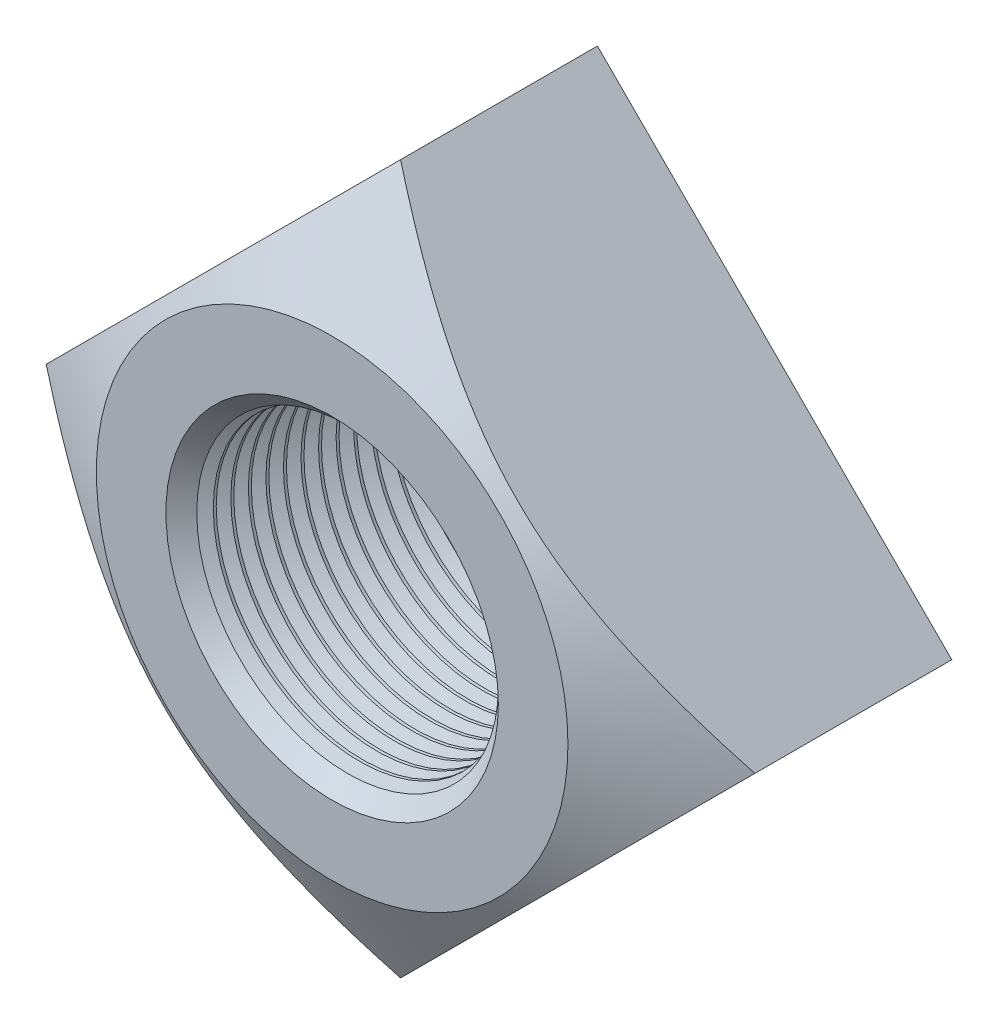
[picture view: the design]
ISO-10303-21;
HEADER;
FILE_DESCRIPTION(('STEP AP214'),'2;1');
FILE_NAME('part.step','',(''),(''),'','','');
FILE_SCHEMA(('AUTOMOTIVE_DESIGN { 1 0 10303 214 1 1 1 1 }'));
ENDSEC;
DATA;
#1=APPLICATION_CONTEXT('core data for automotive mechanical design processes');
#2=APPLICATION_PROTOCOL_DEFINITION('international standard','automotive_design',2000,#1);
#3=PRODUCT_CONTEXT('',#1,'mechanical');
#4=PRODUCT('Part','Part','',(#3));
#5=PRODUCT_RELATED_PRODUCT_CATEGORY('part','',(#4));
#6=PRODUCT_DEFINITION_FORMATION('','',#4);
#7=PRODUCT_DEFINITION_CONTEXT('part definition',#1,'design');
#8=PRODUCT_DEFINITION('design','',#6,#7);
#9=PRODUCT_DEFINITION_SHAPE('','',#8);
#10=(LENGTH_UNIT() NAMED_UNIT(*) SI_UNIT(.MILLI.,.METRE.));
#11=(NAMED_UNIT(*) PLANE_ANGLE_UNIT() SI_UNIT($,.RADIAN.));
#12=(NAMED_UNIT(*) SI_UNIT($,.STERADIAN.) SOLID_ANGLE_UNIT());
#13=UNCERTAINTY_MEASURE_WITH_UNIT(LENGTH_MEASURE(1.E-05),#10,'distance_accuracy_value','');
#14=(GEOMETRIC_REPRESENTATION_CONTEXT(3) GLOBAL_UNCERTAINTY_ASSIGNED_CONTEXT((#13)) GLOBAL_UNIT_ASSIGNED_CONTEXT((#10,
#11,#12)) REPRESENTATION_CONTEXT('',''));
#15=CARTESIAN_POINT('',(0.,0.,0.));
#16=DIRECTION('',(0.,0.,1.));
#17=DIRECTION('',(1.,0.,0.));
#18=AXIS2_PLACEMENT_3D('',#15,#16,#17);
#19=CARTESIAN_POINT('',(0.,0.,-18.));
#20=DIRECTION('',(0.,0.,1.));
#21=DIRECTION('',(1.,0.,0.));
#22=AXIS2_PLACEMENT_3D('',#19,#20,#21);
#23=CYLINDRICAL_SURFACE('',#22,9.9175);
#24=CARTESIAN_POINT('',(0.,0.,-16.64));
#25=DIRECTION('',(0.,0.,1.));
#26=DIRECTION('',(1.,0.,0.));
#27=AXIS2_PLACEMENT_3D('',#24,#25,#26);
#28=CIRCLE('',#27,9.9175);
#29=CARTESIAN_POINT('',(-9.9175,0.,-16.64));
#30=VERTEX_POINT('',#29);
#31=EDGE_CURVE('E50',#30,#30,#28,.F.);
#32=ORIENTED_EDGE('',*,*,#31,.T.);
#33=EDGE_LOOP('',(#32));
#34=FACE_BOUND('',#33,.T.);
#35=CARTESIAN_POINT('',(0.,0.,-16.137075));
#36=DIRECTION('',(0.,0.,-1.));
#37=DIRECTION('',(-1.,0.,0.));
#38=AXIS2_PLACEMENT_3D('',#35,#36,#37);
#39=CIRCLE('',#38,9.9175);
#40=CARTESIAN_POINT('',(-9.9175,0.,-16.137075));
#41=VERTEX_POINT('',#40);
#42=EDGE_CURVE('E641',#41,#41,#39,.T.);
#43=ORIENTED_EDGE('',*,*,#42,.F.);
#44=EDGE_LOOP('',(#43));
#45=FACE_BOUND('',#44,.T.);
#46=ADVANCED_FACE('F41',(#34,#45),#23,.F.);
#47=CARTESIAN_POINT('',(0.,0.,-14.946975));
#48=DIRECTION('',(0.,0.,-1.));
#49=DIRECTION('',(-1.,0.,0.));
#50=AXIS2_PLACEMENT_3D('',#47,#48,#49);
#51=CIRCLE('',#50,9.9175);
#52=CARTESIAN_POINT('',(-9.9175,0.,-14.946975));
#53=VERTEX_POINT('',#52);
#54=EDGE_CURVE('E652',#53,#53,#51,.T.);
#55=ORIENTED_EDGE('',*,*,#54,.F.);
#56=EDGE_LOOP('',(#55));
#57=FACE_BOUND('',#56,.T.);
#58=CARTESIAN_POINT('',(0.,0.,-15.145325));
#59=DIRECTION('',(0.,0.,-1.));
#60=DIRECTION('',(-1.,0.,0.));
#61=AXIS2_PLACEMENT_3D('',#58,#59,#60);
#62=CIRCLE('',#61,9.9175);
#63=CARTESIAN_POINT('',(-9.9175,0.,-15.145325));
#64=VERTEX_POINT('',#63);
#65=EDGE_CURVE('E638',#64,#64,#62,.T.);
#66=ORIENTED_EDGE('',*,*,#65,.T.);
#67=EDGE_LOOP('',(#66));
#68=FACE_BOUND('',#67,.T.);
#69=ADVANCED_FACE('F186',(#57,#68),#23,.F.);
#70=CARTESIAN_POINT('',(0.,0.,-13.756875));
#71=DIRECTION('',(0.,0.,-1.));
#72=DIRECTION('',(-1.,0.,0.));
#73=AXIS2_PLACEMENT_3D('',#70,#71,#72);
#74=CIRCLE('',#73,9.9175);
#75=CARTESIAN_POINT('',(-9.9175,0.,-13.756875));
#76=VERTEX_POINT('',#75);
#77=EDGE_CURVE('E661',#76,#76,#74,.T.);
#78=ORIENTED_EDGE('',*,*,#77,.F.);
#79=EDGE_LOOP('',(#78));
#80=FACE_BOUND('',#79,.T.);
#81=CARTESIAN_POINT('',(0.,0.,-13.955225));
#82=DIRECTION('',(0.,0.,-1.));
#83=DIRECTION('',(-1.,0.,0.));
#84=AXIS2_PLACEMENT_3D('',#81,#82,#83);
#85=CIRCLE('',#84,9.9175);
#86=CARTESIAN_POINT('',(-9.9175,0.,-13.955225));
#87=VERTEX_POINT('',#86);
#88=EDGE_CURVE('E646',#87,#87,#85,.T.);
#89=ORIENTED_EDGE('',*,*,#88,.T.);
#90=EDGE_LOOP('',(#89));
#91=FACE_BOUND('',#90,.T.);
#92=ADVANCED_FACE('F192',(#80,#91),#23,.F.);
#93=CARTESIAN_POINT('',(0.,0.,-12.566775));
#94=DIRECTION('',(0.,0.,-1.));
#95=DIRECTION('',(-1.,0.,0.));
#96=AXIS2_PLACEMENT_3D('',#93,#94,#95);
#97=CIRCLE('',#96,9.9175);
#98=CARTESIAN_POINT('',(-9.9175,0.,-12.566775));
#99=VERTEX_POINT('',#98);
#100=EDGE_CURVE('E670',#99,#99,#97,.T.);
#101=ORIENTED_EDGE('',*,*,#100,.F.);
#102=EDGE_LOOP('',(#101));
#103=FACE_BOUND('',#102,.T.);
#104=CARTESIAN_POINT('',(0.,0.,-12.765125));
#105=DIRECTION('',(0.,0.,-1.));
#106=DIRECTION('',(-1.,0.,0.));
#107=AXIS2_PLACEMENT_3D('',#104,#105,#106);
#108=CIRCLE('',#107,9.9175);
#109=CARTESIAN_POINT('',(-9.9175,0.,-12.765125));
#110=VERTEX_POINT('',#109);
#111=EDGE_CURVE('E655',#110,#110,#108,.T.);
#112=ORIENTED_EDGE('',*,*,#111,.T.);
#113=EDGE_LOOP('',(#112));
#114=FACE_BOUND('',#113,.T.);
#115=ADVANCED_FACE('F319',(#103,#114),#23,.F.);
#116=CARTESIAN_POINT('',(0.,0.,-11.376675));
#117=DIRECTION('',(0.,0.,-1.));
#118=DIRECTION('',(-1.,0.,0.));
#119=AXIS2_PLACEMENT_3D('',#116,#117,#118);
#120=CIRCLE('',#119,9.9175);
#121=CARTESIAN_POINT('',(-9.9175,0.,-11.376675));
#122=VERTEX_POINT('',#121);
#123=EDGE_CURVE('E679',#122,#122,#120,.T.);
#124=ORIENTED_EDGE('',*,*,#123,.F.);
#125=EDGE_LOOP('',(#124));
#126=FACE_BOUND('',#125,.T.);
#127=CARTESIAN_POINT('',(0.,0.,-11.575025));
#128=DIRECTION('',(0.,0.,-1.));
#129=DIRECTION('',(-1.,0.,0.));
#130=AXIS2_PLACEMENT_3D('',#127,#128,#129);
#131=CIRCLE('',#130,9.9175);
#132=CARTESIAN_POINT('',(-9.9175,0.,-11.575025));
#133=VERTEX_POINT('',#132);
#134=EDGE_CURVE('E664',#133,#133,#131,.T.);
#135=ORIENTED_EDGE('',*,*,#134,.T.);
#136=EDGE_LOOP('',(#135));
#137=FACE_BOUND('',#136,.T.);
#138=ADVANCED_FACE('F311',(#126,#137),#23,.F.);
#139=CARTESIAN_POINT('',(0.,0.,-10.186575));
#140=DIRECTION('',(0.,0.,-1.));
#141=DIRECTION('',(-1.,0.,0.));
#142=AXIS2_PLACEMENT_3D('',#139,#140,#141);
#143=CIRCLE('',#142,9.9175);
#144=CARTESIAN_POINT('',(-9.9175,0.,-10.186575));
#145=VERTEX_POINT('',#144);
#146=EDGE_CURVE('E688',#145,#145,#143,.T.);
#147=ORIENTED_EDGE('',*,*,#146,.F.);
#148=EDGE_LOOP('',(#147));
#149=FACE_BOUND('',#148,.T.);
#150=CARTESIAN_POINT('',(0.,0.,-10.384925));
#151=DIRECTION('',(0.,0.,-1.));
#152=DIRECTION('',(-1.,0.,0.));
#153=AXIS2_PLACEMENT_3D('',#150,#151,#152);
#154=CIRCLE('',#153,9.9175);
#155=CARTESIAN_POINT('',(-9.9175,0.,-10.384925));
#156=VERTEX_POINT('',#155);
#157=EDGE_CURVE('E673',#156,#156,#154,.T.);
#158=ORIENTED_EDGE('',*,*,#157,.T.);
#159=EDGE_LOOP('',(#158));
#160=FACE_BOUND('',#159,.T.);
#161=ADVANCED_FACE('F302',(#149,#160),#23,.F.);
#162=CARTESIAN_POINT('',(0.,0.,-8.996475));
#163=DIRECTION('',(0.,0.,-1.));
#164=DIRECTION('',(-1.,0.,0.));
#165=AXIS2_PLACEMENT_3D('',#162,#163,#164);
#166=CIRCLE('',#165,9.9175);
#167=CARTESIAN_POINT('',(-9.9175,0.,-8.996475));
#168=VERTEX_POINT('',#167);
#169=EDGE_CURVE('E697',#168,#168,#166,.T.);
#170=ORIENTED_EDGE('',*,*,#169,.F.);
#171=EDGE_LOOP('',(#170));
#172=FACE_BOUND('',#171,.T.);
#173=CARTESIAN_POINT('',(0.,0.,-9.194825));
#174=DIRECTION('',(0.,0.,-1.));
#175=DIRECTION('',(-1.,0.,0.));
#176=AXIS2_PLACEMENT_3D('',#173,#174,#175);
#177=CIRCLE('',#176,9.9175);
#178=CARTESIAN_POINT('',(-9.9175,0.,-9.194825));
#179=VERTEX_POINT('',#178);
#180=EDGE_CURVE('E682',#179,#179,#177,.T.);
#181=ORIENTED_EDGE('',*,*,#180,.T.);
#182=EDGE_LOOP('',(#181));
#183=FACE_BOUND('',#182,.T.);
#184=ADVANCED_FACE('F294',(#172,#183),#23,.F.);
#185=CARTESIAN_POINT('',(0.,0.,-7.806375));
#186=DIRECTION('',(0.,0.,-1.));
#187=DIRECTION('',(-1.,0.,0.));
#188=AXIS2_PLACEMENT_3D('',#185,#186,#187);
#189=CIRCLE('',#188,9.9175);
#190=CARTESIAN_POINT('',(-9.9175,0.,-7.806375));
#191=VERTEX_POINT('',#190);
#192=EDGE_CURVE('E706',#191,#191,#189,.T.);
#193=ORIENTED_EDGE('',*,*,#192,.F.);
#194=EDGE_LOOP('',(#193));
#195=FACE_BOUND('',#194,.T.);
#196=CARTESIAN_POINT('',(0.,0.,-8.004725));
#197=DIRECTION('',(0.,0.,-1.));
#198=DIRECTION('',(-1.,0.,0.));
#199=AXIS2_PLACEMENT_3D('',#196,#197,#198);
#200=CIRCLE('',#199,9.9175);
#201=CARTESIAN_POINT('',(-9.9175,0.,-8.004725));
#202=VERTEX_POINT('',#201);
#203=EDGE_CURVE('E691',#202,#202,#200,.T.);
#204=ORIENTED_EDGE('',*,*,#203,.T.);
#205=EDGE_LOOP('',(#204));
#206=FACE_BOUND('',#205,.T.);
#207=ADVANCED_FACE('F285',(#195,#206),#23,.F.);
#208=CARTESIAN_POINT('',(0.,0.,-6.616275));
#209=DIRECTION('',(0.,0.,-1.));
#210=DIRECTION('',(-1.,0.,0.));
#211=AXIS2_PLACEMENT_3D('',#208,#209,#210);
#212=CIRCLE('',#211,9.9175);
#213=CARTESIAN_POINT('',(-9.9175,0.,-6.616275));
#214=VERTEX_POINT('',#213);
#215=EDGE_CURVE('E715',#214,#214,#212,.T.);
#216=ORIENTED_EDGE('',*,*,#215,.F.);
#217=EDGE_LOOP('',(#216));
#218=FACE_BOUND('',#217,.T.);
#219=CARTESIAN_POINT('',(0.,0.,-6.814625));
#220=DIRECTION('',(0.,0.,-1.));
#221=DIRECTION('',(-1.,0.,0.));
#222=AXIS2_PLACEMENT_3D('',#219,#220,#221);
#223=CIRCLE('',#222,9.9175);
#224=CARTESIAN_POINT('',(-9.9175,0.,-6.814625));
#225=VERTEX_POINT('',#224);
#226=EDGE_CURVE('E700',#225,#225,#223,.T.);
#227=ORIENTED_EDGE('',*,*,#226,.T.);
#228=EDGE_LOOP('',(#227));
#229=FACE_BOUND('',#228,.T.);
#230=ADVANCED_FACE('F277',(#218,#229),#23,.F.);
#231=CARTESIAN_POINT('',(0.,0.,-5.426175));
#232=DIRECTION('',(0.,0.,-1.));
#233=DIRECTION('',(-1.,0.,0.));
#234=AXIS2_PLACEMENT_3D('',#231,#232,#233);
#235=CIRCLE('',#234,9.9175);
#236=CARTESIAN_POINT('',(-9.9175,0.,-5.426175));
#237=VERTEX_POINT('',#236);
#238=EDGE_CURVE('E724',#237,#237,#235,.T.);
#239=ORIENTED_EDGE('',*,*,#238,.F.);
#240=EDGE_LOOP('',(#239));
#241=FACE_BOUND('',#240,.T.);
#242=CARTESIAN_POINT('',(0.,0.,-5.624525));
#243=DIRECTION('',(0.,0.,-1.));
#244=DIRECTION('',(-1.,0.,0.));
#245=AXIS2_PLACEMENT_3D('',#242,#243,#244);
#246=CIRCLE('',#245,9.9175);
#247=CARTESIAN_POINT('',(-9.9175,0.,-5.624525));
#248=VERTEX_POINT('',#247);
#249=EDGE_CURVE('E709',#248,#248,#246,.T.);
#250=ORIENTED_EDGE('',*,*,#249,.T.);
#251=EDGE_LOOP('',(#250));
#252=FACE_BOUND('',#251,.T.);
#253=ADVANCED_FACE('F268',(#241,#252),#23,.F.);
#254=CARTESIAN_POINT('',(0.,0.,-4.236075));
#255=DIRECTION('',(0.,0.,-1.));
#256=DIRECTION('',(-1.,0.,0.));
#257=AXIS2_PLACEMENT_3D('',#254,#255,#256);
#258=CIRCLE('',#257,9.9175);
#259=CARTESIAN_POINT('',(-9.9175,0.,-4.236075));
#260=VERTEX_POINT('',#259);
#261=EDGE_CURVE('E214',#260,#260,#258,.T.);
#262=ORIENTED_EDGE('',*,*,#261,.F.);
#263=EDGE_LOOP('',(#262));
#264=FACE_BOUND('',#263,.T.);
#265=CARTESIAN_POINT('',(0.,0.,-4.434425));
#266=DIRECTION('',(0.,0.,-1.));
#267=DIRECTION('',(-1.,0.,0.));
#268=AXIS2_PLACEMENT_3D('',#265,#266,#267);
#269=CIRCLE('',#268,9.9175);
#270=CARTESIAN_POINT('',(-9.9175,0.,-4.434425));
#271=VERTEX_POINT('',#270);
#272=EDGE_CURVE('E718',#271,#271,#269,.T.);
#273=ORIENTED_EDGE('',*,*,#272,.T.);
#274=EDGE_LOOP('',(#273));
#275=FACE_BOUND('',#274,.T.);
#276=ADVANCED_FACE('F203',(#264,#275),#23,.F.);
#277=CARTESIAN_POINT('',(0.,0.,-3.045975));
#278=DIRECTION('',(0.,0.,-1.));
#279=DIRECTION('',(-1.,0.,0.));
#280=AXIS2_PLACEMENT_3D('',#277,#278,#279);
#281=CIRCLE('',#280,9.9175);
#282=CARTESIAN_POINT('',(-9.9175,0.,-3.045975));
#283=VERTEX_POINT('',#282);
#284=EDGE_CURVE('E217',#283,#283,#281,.T.);
#285=ORIENTED_EDGE('',*,*,#284,.F.);
#286=EDGE_LOOP('',(#285));
#287=FACE_BOUND('',#286,.T.);
#288=CARTESIAN_POINT('',(0.,0.,-3.244325));
#289=DIRECTION('',(0.,0.,-1.));
#290=DIRECTION('',(-1.,0.,0.));
#291=AXIS2_PLACEMENT_3D('',#288,#289,#290);
#292=CIRCLE('',#291,9.9175);
#293=CARTESIAN_POINT('',(-9.9175,0.,-3.244325));
#294=VERTEX_POINT('',#293);
#295=EDGE_CURVE('E727',#294,#294,#292,.T.);
#296=ORIENTED_EDGE('',*,*,#295,.T.);
#297=EDGE_LOOP('',(#296));
#298=FACE_BOUND('',#297,.T.);
#299=ADVANCED_FACE('F195',(#287,#298),#23,.F.);
#300=CARTESIAN_POINT('',(0.,0.,-1.855875));
#301=DIRECTION('',(0.,0.,-1.));
#302=DIRECTION('',(-1.,0.,0.));
#303=AXIS2_PLACEMENT_3D('',#300,#301,#302);
#304=CIRCLE('',#303,9.9175);
#305=CARTESIAN_POINT('',(-9.9175,0.,-1.855875));
#306=VERTEX_POINT('',#305);
#307=EDGE_CURVE('E208',#306,#306,#304,.T.);
#308=ORIENTED_EDGE('',*,*,#307,.F.);
#309=EDGE_LOOP('',(#308));
#310=FACE_BOUND('',#309,.T.);
#311=CARTESIAN_POINT('',(0.,0.,-2.054225));
#312=DIRECTION('',(0.,0.,-1.));
#313=DIRECTION('',(-1.,0.,0.));
#314=AXIS2_PLACEMENT_3D('',#311,#312,#313);
#315=CIRCLE('',#314,9.9175);
#316=CARTESIAN_POINT('',(-9.9175,0.,-2.054225));
#317=VERTEX_POINT('',#316);
#318=EDGE_CURVE('E211',#317,#317,#315,.T.);
#319=ORIENTED_EDGE('',*,*,#318,.T.);
#320=EDGE_LOOP('',(#319));
#321=FACE_BOUND('',#320,.T.);
#322=ADVANCED_FACE('F187',(#310,#321),#23,.F.);
#323=CARTESIAN_POINT('',(0.,0.,-1.36000000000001));
#324=DIRECTION('',(0.,0.,1.));
#325=DIRECTION('',(1.,0.,0.));
#326=AXIS2_PLACEMENT_3D('',#323,#324,#325);
#327=CONICAL_SURFACE('',#326,9.9175,0.785398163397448);
#328=CARTESIAN_POINT('',(0.,0.,0.));
#329=DIRECTION('',(0.,0.,1.));
#330=DIRECTION('',(1.,0.,0.));
#331=AXIS2_PLACEMENT_3D('',#328,#329,#330);
#332=CIRCLE('',#331,11.2775);
#333=CARTESIAN_POINT('',(11.2775,0.,0.));
#334=VERTEX_POINT('',#333);
#335=EDGE_CURVE('E11',#334,#334,#332,.F.);
#336=CARTESIAN_POINT('',(0.,0.,-1.04562784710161));
#337=DIRECTION('',(0.,0.,-1.));
#338=DIRECTION('',(-1.,0.,0.));
#339=AXIS2_PLACEMENT_3D('',#336,#337,#338);
#340=CIRCLE('',#339,10.2318721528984);
#341=CARTESIAN_POINT('',(10.2318721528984,0.,-1.04562784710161));
#342=VERTEX_POINT('',#341);
#343=EDGE_CURVE('E45',#342,#342,#340,.T.);
#344=CARTESIAN_POINT('',(11.2775,0.,0.));
#345=CARTESIAN_POINT('',(11.2666080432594,0.,-0.010891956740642));
#346=CARTESIAN_POINT('',(11.2557160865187,0.,-0.0217839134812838));
#347=CARTESIAN_POINT('',(11.2339321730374,0.,-0.0435678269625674));
#348=CARTESIAN_POINT('',(11.2230402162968,0.,-0.0544597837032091));
#349=CARTESIAN_POINT('',(11.2012563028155,0.,-0.0762436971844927));
#350=CARTESIAN_POINT('',(11.1903643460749,0.,-0.0871356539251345));
#351=CARTESIAN_POINT('',(11.1685804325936,0.,-0.108919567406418));
#352=CARTESIAN_POINT('',(11.157688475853,0.,-0.11981152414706));
#353=CARTESIAN_POINT('',(11.1359045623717,0.,-0.141595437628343));
#354=CARTESIAN_POINT('',(11.125012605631,0.,-0.152487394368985));
#355=CARTESIAN_POINT('',(11.1032286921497,0.,-0.174271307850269));
#356=CARTESIAN_POINT('',(11.0923367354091,0.,-0.18516326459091));
#357=CARTESIAN_POINT('',(11.0705528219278,0.,-0.206947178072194));
#358=CARTESIAN_POINT('',(11.0596608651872,0.,-0.217839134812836));
#359=CARTESIAN_POINT('',(11.0378769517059,0.,-0.23962304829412));
#360=CARTESIAN_POINT('',(11.0269849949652,0.,-0.250515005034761));
#361=CARTESIAN_POINT('',(11.005201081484,0.,-0.272298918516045));
#362=CARTESIAN_POINT('',(10.9943091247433,0.,-0.283190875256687));
#363=CARTESIAN_POINT('',(10.972525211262,0.,-0.30497478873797));
#364=CARTESIAN_POINT('',(10.9616332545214,0.,-0.315866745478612));
#365=CARTESIAN_POINT('',(10.9398493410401,0.,-0.337650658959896));
#366=CARTESIAN_POINT('',(10.9289573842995,0.,-0.348542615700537));
#367=CARTESIAN_POINT('',(10.9071734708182,0.,-0.370326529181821));
#368=CARTESIAN_POINT('',(10.8962815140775,0.,-0.381218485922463));
#369=CARTESIAN_POINT('',(10.8744976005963,0.,-0.403002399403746));
#370=CARTESIAN_POINT('',(10.8636056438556,0.,-0.413894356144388));
#371=CARTESIAN_POINT('',(10.8418217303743,0.,-0.435678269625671));
#372=CARTESIAN_POINT('',(10.8309297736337,0.,-0.446570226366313));
#373=CARTESIAN_POINT('',(10.8091458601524,0.,-0.468354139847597));
#374=CARTESIAN_POINT('',(10.7982539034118,0.,-0.479246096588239));
#375=CARTESIAN_POINT('',(10.7764699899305,0.,-0.501030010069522));
#376=CARTESIAN_POINT('',(10.7655780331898,0.,-0.511921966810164));
#377=CARTESIAN_POINT('',(10.7437941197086,0.,-0.533705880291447));
#378=CARTESIAN_POINT('',(10.7329021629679,0.,-0.544597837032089));
#379=CARTESIAN_POINT('',(10.7111182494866,0.,-0.566381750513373));
#380=CARTESIAN_POINT('',(10.700226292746,0.,-0.577273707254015));
#381=CARTESIAN_POINT('',(10.6784423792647,0.,-0.599057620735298));
#382=CARTESIAN_POINT('',(10.6675504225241,0.,-0.60994957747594));
#383=CARTESIAN_POINT('',(10.6457665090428,0.,-0.631733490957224));
#384=CARTESIAN_POINT('',(10.6348745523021,0.,-0.642625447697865));
#385=CARTESIAN_POINT('',(10.6130906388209,0.,-0.664409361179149));
#386=CARTESIAN_POINT('',(10.6021986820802,0.,-0.675301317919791));
#387=CARTESIAN_POINT('',(10.5804147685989,0.,-0.697085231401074));
#388=CARTESIAN_POINT('',(10.5695228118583,0.,-0.707977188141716));
#389=CARTESIAN_POINT('',(10.547738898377,0.,-0.729761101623));
#390=CARTESIAN_POINT('',(10.5368469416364,0.,-0.740653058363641));
#391=CARTESIAN_POINT('',(10.5150630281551,0.,-0.762436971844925));
#392=CARTESIAN_POINT('',(10.5041710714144,0.,-0.773328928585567));
#393=CARTESIAN_POINT('',(10.4823871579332,0.,-0.79511284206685));
#394=CARTESIAN_POINT('',(10.4714952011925,0.,-0.806004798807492));
#395=CARTESIAN_POINT('',(10.4497112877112,0.,-0.827788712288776));
#396=CARTESIAN_POINT('',(10.4388193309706,0.,-0.838680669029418));
#397=CARTESIAN_POINT('',(10.4170354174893,0.,-0.860464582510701));
#398=CARTESIAN_POINT('',(10.4061434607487,0.,-0.871356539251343));
#399=CARTESIAN_POINT('',(10.3843595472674,0.,-0.893140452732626));
#400=CARTESIAN_POINT('',(10.3734675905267,0.,-0.904032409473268));
#401=CARTESIAN_POINT('',(10.3516836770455,0.,-0.925816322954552));
#402=CARTESIAN_POINT('',(10.3407917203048,0.,-0.936708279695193));
#403=CARTESIAN_POINT('',(10.3190078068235,0.,-0.958492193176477));
#404=CARTESIAN_POINT('',(10.3081158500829,0.,-0.969384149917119));
#405=CARTESIAN_POINT('',(10.2863319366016,0.,-0.991168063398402));
#406=CARTESIAN_POINT('',(10.275439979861,0.,-1.00206002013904));
#407=CARTESIAN_POINT('',(10.2536560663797,0.,-1.02384393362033));
#408=CARTESIAN_POINT('',(10.242764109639,0.,-1.03473589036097));
#409=CARTESIAN_POINT('',(10.2318721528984,0.,-1.04562784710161));
#410=B_SPLINE_CURVE_WITH_KNOTS('',3,(#344,#345,#346,#347,#348,#349,#350,#351,#352,#353,#354,
#355,#356,#357,#358,#359,#360,#361,#362,#363,#364,#365,#366,#367,#368,#369,#370,#371,#372,#373,
#374,#375,#376,#377,#378,#379,#380,#381,#382,#383,#384,#385,#386,#387,#388,#389,#390,#391,#392,
#393,#394,#395,#396,#397,#398,#399,#400,#401,#402,#403,#404,#405,#406,#407,#408,#409),
.UNSPECIFIED.,.F.,.F.,(4,2,2,2,2,2,2,2,2,2,2,2,2,2,2,2,2,2,2,2,2,2,2,2,2,2,2,2,2,2,2,2,4),(0.,
0.0462106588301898,0.0924213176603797,0.13863197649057,0.184842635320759,0.231053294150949,
0.27726395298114,0.32347461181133,0.36968527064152,0.41589592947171,0.4621065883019,
0.508317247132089,0.554527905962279,0.600738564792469,0.646949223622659,0.693159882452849,
0.73937054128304,0.78558120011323,0.831791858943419,0.878002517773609,0.924213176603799,
0.970423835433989,1.01663449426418,1.06284515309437,1.10905581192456,1.15526647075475,
1.20147712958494,1.24768778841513,1.29389844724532,1.34010910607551,1.3863197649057,
1.43253042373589,1.47874108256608),.UNSPECIFIED.);
#411=EDGE_CURVE('BSEAM43',#334,#342,#410,.T.);
#412=ORIENTED_EDGE('',*,*,#335,.F.);
#413=ORIENTED_EDGE('',*,*,#343,.T.);
#414=ORIENTED_EDGE('',*,*,#411,.T.);
#415=ORIENTED_EDGE('',*,*,#411,.F.);
#416=EDGE_LOOP('',(#412,#414,#413,#415));
#417=FACE_BOUND('',#416,.T.);
#418=ADVANCED_FACE('F43',(#417),#327,.F.);
#419=CARTESIAN_POINT('',(24.0416305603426,0.,-18.));
#420=DIRECTION('',(0.707106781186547,0.707106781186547,0.));
#421=DIRECTION('',(-0.707106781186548,0.707106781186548,0.));
#422=AXIS2_PLACEMENT_3D('',#419,#420,#421);
#423=PLANE('',#422);
#424=DIRECTION('',(0.,0.,1.));
#425=VECTOR('',#424,1.);
#426=CARTESIAN_POINT('',(0.,24.0416305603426,-18.));
#427=LINE('',#426,#425);
#428=CARTESIAN_POINT('',(0.,24.0416305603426,-18.));
#429=VERTEX_POINT('',#428);
#430=CARTESIAN_POINT('',(0.,24.0416305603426,-4.64283756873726));
#431=VERTEX_POINT('',#430);
#432=EDGE_CURVE('E92',#429,#431,#427,.T.);
#433=ORIENTED_EDGE('',*,*,#432,.T.);
#434=CARTESIAN_POINT('',(-0.0002,24.0418305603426,-4.64295303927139));
#435=CARTESIAN_POINT('',(0.204179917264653,23.837450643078,-4.52495674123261));
#436=CARTESIAN_POINT('',(0.408930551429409,23.6327000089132,-4.40824356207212));
#437=CARTESIAN_POINT('',(0.819230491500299,23.2224000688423,-4.1776440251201));
#438=CARTESIAN_POINT('',(1.02477981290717,23.0168507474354,-4.06375772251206));
#439=CARTESIAN_POINT('',(1.64283390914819,22.3987966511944,-3.72666365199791));
#440=CARTESIAN_POINT('',(2.05661170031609,21.9850188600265,-3.50809795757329));
#441=CARTESIAN_POINT('',(2.89055315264,21.1510774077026,-3.08458280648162));
#442=CARTESIAN_POINT('',(3.3107404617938,20.7308900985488,-2.87972567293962));
#443=CARTESIAN_POINT('',(4.15527812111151,19.8863524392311,-2.4883165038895));
#444=CARTESIAN_POINT('',(4.57962811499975,19.4620024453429,-2.30176291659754));
#445=CARTESIAN_POINT('',(5.84524248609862,18.196388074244,-1.78094350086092));
#446=CARTESIAN_POINT('',(6.69335424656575,17.3482763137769,-1.47802223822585));
#447=CARTESIAN_POINT('',(7.97712947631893,16.0645010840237,-1.11263624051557));
#448=CARTESIAN_POINT('',(8.40653302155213,15.6350975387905,-1.00573915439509));
#449=CARTESIAN_POINT('',(9.26888168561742,14.7727488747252,-0.825515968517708));
#450=CARTESIAN_POINT('',(9.70182641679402,14.3398041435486,-0.752186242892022));
#451=CARTESIAN_POINT('',(10.4991978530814,13.5424327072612,-0.65132723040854));
#452=CARTESIAN_POINT('',(10.8632772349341,13.1783533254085,-0.618276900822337));
#453=CARTESIAN_POINT('',(11.592162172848,12.4494683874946,-0.579101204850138));
#454=CARTESIAN_POINT('',(11.9569677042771,12.0846628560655,-0.572974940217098));
#455=CARTESIAN_POINT('',(12.686458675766,11.3551718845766,-0.587874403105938));
#456=CARTESIAN_POINT('',(13.0511439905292,10.9904865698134,-0.608912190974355));
#457=CARTESIAN_POINT('',(13.7792651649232,10.2623653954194,-0.677412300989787));
#458=CARTESIAN_POINT('',(14.1427010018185,9.89892955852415,-0.724875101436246));
#459=CARTESIAN_POINT('',(14.868134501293,9.17349605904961,-0.844749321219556));
#460=CARTESIAN_POINT('',(15.2301285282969,8.81150203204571,-0.917204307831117));
#461=CARTESIAN_POINT('',(15.9514546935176,8.09017586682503,-1.08487407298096));
#462=CARTESIAN_POINT('',(16.3107867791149,7.73084378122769,-1.180089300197));
#463=CARTESIAN_POINT('',(17.0264920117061,7.01513854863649,-1.39082723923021));
#464=CARTESIAN_POINT('',(17.3828647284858,6.6587658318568,-1.50635285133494));
#465=CARTESIAN_POINT('',(18.0924606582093,5.94916990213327,-1.75518740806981));
#466=CARTESIAN_POINT('',(18.44568394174,5.59594661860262,-1.88849595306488));
#467=CARTESIAN_POINT('',(19.244654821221,4.79697573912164,-2.20884892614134));
#468=CARTESIAN_POINT('',(19.689446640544,4.35218391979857,-2.4006487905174));
#469=CARTESIAN_POINT('',(20.5741726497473,3.46745791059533,-2.80469605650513));
#470=CARTESIAN_POINT('',(21.0141082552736,3.02752230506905,-3.01693731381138));
#471=CARTESIAN_POINT('',(21.8874677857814,2.15416277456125,-3.45710309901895));
#472=CARTESIAN_POINT('',(22.3209135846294,1.72071697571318,-3.68494116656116));
#473=CARTESIAN_POINT('',(22.968274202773,1.07335635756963,-4.03695781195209));
#474=CARTESIAN_POINT('',(23.1835948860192,0.858035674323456,-4.15600767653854));
#475=CARTESIAN_POINT('',(23.6133557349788,0.428274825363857,-4.39722047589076));
#476=CARTESIAN_POINT('',(23.8277959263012,0.213834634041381,-4.5193833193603));
#477=CARTESIAN_POINT('',(24.0418305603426,-0.000199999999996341,-4.64295303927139));
#478=B_SPLINE_CURVE_WITH_KNOTS('',3,(#434,#435,#436,#437,#438,#439,#440,#441,#442,#443,#444,
#445,#446,#447,#448,#449,#450,#451,#452,#453,#454,#455,#456,#457,#458,#459,#460,#461,#462,#463,
#464,#465,#466,#467,#468,#469,#470,#471,#472,#473,#474,#475,#476,#477),.UNSPECIFIED.,.F.,.F.,(4,
2,2,2,2,2,2,2,2,2,2,2,2,2,2,2,2,2,2,2,2,4),(0.,0.936579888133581,1.8731780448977,
3.74698468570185,5.6323516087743,7.51755855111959,11.2234409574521,13.0725100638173,
14.9213793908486,16.4685561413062,18.0156812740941,19.5634935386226,21.1113338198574,
22.6618861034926,24.2124689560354,25.7632734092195,27.3140430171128,29.2864587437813,
31.2582834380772,33.2199463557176,34.200794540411,35.1816139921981),.UNSPECIFIED.);
#479=CARTESIAN_POINT('',(24.0416305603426,0.,-4.64283756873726));
#480=VERTEX_POINT('',#479);
#481=EDGE_CURVE('E57',#431,#480,#478,.T.);
#482=ORIENTED_EDGE('',*,*,#481,.T.);
#483=DIRECTION('',(0.,0.,1.));
#484=VECTOR('',#483,1.);
#485=CARTESIAN_POINT('',(24.0416305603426,0.,-18.));
#486=LINE('',#485,#484);
#487=CARTESIAN_POINT('',(24.0416305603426,0.,-18.));
#488=VERTEX_POINT('',#487);
#489=EDGE_CURVE('E64',#488,#480,#486,.T.);
#490=ORIENTED_EDGE('',*,*,#489,.F.);
#491=DIRECTION('',(-0.707106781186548,0.707106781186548,0.));
#492=VECTOR('',#491,1.);
#493=CARTESIAN_POINT('',(24.0416305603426,0.,-18.));
#494=LINE('',#493,#492);
#495=EDGE_CURVE('E93',#488,#429,#494,.T.);
#496=ORIENTED_EDGE('',*,*,#495,.T.);
#497=EDGE_LOOP('',(#433,#482,#490,#496));
#498=FACE_BOUND('',#497,.T.);
#499=ADVANCED_FACE('F91',(#498),#423,.T.);
#500=CARTESIAN_POINT('',(0.,-24.0416305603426,-18.));
#501=DIRECTION('',(0.707106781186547,-0.707106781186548,0.));
#502=DIRECTION('',(0.707106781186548,0.707106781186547,0.));
#503=AXIS2_PLACEMENT_3D('',#500,#501,#502);
#504=PLANE('',#503);
#505=ORIENTED_EDGE('',*,*,#489,.T.);
#506=CARTESIAN_POINT('',(24.0418305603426,0.000200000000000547,-4.64295303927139));
#507=CARTESIAN_POINT('',(23.837450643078,-0.204179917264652,-4.52495674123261));
#508=CARTESIAN_POINT('',(23.6327000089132,-0.408930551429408,-4.40824356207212));
#509=CARTESIAN_POINT('',(23.2224000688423,-0.819230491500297,-4.1776440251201));
#510=CARTESIAN_POINT('',(23.0168507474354,-1.02477981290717,-4.06375772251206));
#511=CARTESIAN_POINT('',(22.3987966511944,-1.64283390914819,-3.72666365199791));
#512=CARTESIAN_POINT('',(21.9850188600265,-2.05661170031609,-3.50809795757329));
#513=CARTESIAN_POINT('',(21.1510774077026,-2.89055315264,-3.08458280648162));
#514=CARTESIAN_POINT('',(20.7308900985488,-3.3107404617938,-2.87972567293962));
#515=CARTESIAN_POINT('',(19.8863524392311,-4.15527812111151,-2.4883165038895));
#516=CARTESIAN_POINT('',(19.4620024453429,-4.57962811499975,-2.30176291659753));
#517=CARTESIAN_POINT('',(18.196388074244,-5.84524248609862,-1.78094350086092));
#518=CARTESIAN_POINT('',(17.3482763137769,-6.69335424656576,-1.47802223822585));
#519=CARTESIAN_POINT('',(16.0645010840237,-7.97712947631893,-1.11263624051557));
#520=CARTESIAN_POINT('',(15.6350975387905,-8.40653302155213,-1.0057391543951));
#521=CARTESIAN_POINT('',(14.7727488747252,-9.26888168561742,-0.825515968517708));
#522=CARTESIAN_POINT('',(14.3398041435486,-9.70182641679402,-0.752186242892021));
#523=CARTESIAN_POINT('',(13.5424327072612,-10.4991978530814,-0.651327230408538));
#524=CARTESIAN_POINT('',(13.1783533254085,-10.8632772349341,-0.618276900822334));
#525=CARTESIAN_POINT('',(12.4494683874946,-11.592162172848,-0.579101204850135));
#526=CARTESIAN_POINT('',(12.0846628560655,-11.9569677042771,-0.572974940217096));
#527=CARTESIAN_POINT('',(11.3551718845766,-12.686458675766,-0.587874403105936));
#528=CARTESIAN_POINT('',(10.9904865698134,-13.0511439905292,-0.608912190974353));
#529=CARTESIAN_POINT('',(10.2623653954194,-13.7792651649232,-0.677412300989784));
#530=CARTESIAN_POINT('',(9.89892955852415,-14.1427010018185,-0.724875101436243));
#531=CARTESIAN_POINT('',(9.17349605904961,-14.868134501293,-0.844749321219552));
#532=CARTESIAN_POINT('',(8.81150203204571,-15.2301285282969,-0.917204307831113));
#533=CARTESIAN_POINT('',(8.09017586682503,-15.9514546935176,-1.08487407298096));
#534=CARTESIAN_POINT('',(7.73084378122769,-16.3107867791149,-1.18008930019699));
#535=CARTESIAN_POINT('',(7.01513854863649,-17.0264920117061,-1.3908272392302));
#536=CARTESIAN_POINT('',(6.6587658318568,-17.3828647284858,-1.50635285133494));
#537=CARTESIAN_POINT('',(5.94916990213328,-18.0924606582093,-1.7551874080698));
#538=CARTESIAN_POINT('',(5.59594661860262,-18.44568394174,-1.88849595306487));
#539=CARTESIAN_POINT('',(4.79697573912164,-19.244654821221,-2.20884892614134));
#540=CARTESIAN_POINT('',(4.35218391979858,-19.689446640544,-2.4006487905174));
#541=CARTESIAN_POINT('',(3.46745791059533,-20.5741726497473,-2.80469605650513));
#542=CARTESIAN_POINT('',(3.02752230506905,-21.0141082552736,-3.01693731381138));
#543=CARTESIAN_POINT('',(2.15416277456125,-21.8874677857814,-3.45710309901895));
#544=CARTESIAN_POINT('',(1.72071697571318,-22.3209135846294,-3.68494116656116));
#545=CARTESIAN_POINT('',(1.07335635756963,-22.968274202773,-4.03695781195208));
#546=CARTESIAN_POINT('',(0.858035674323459,-23.1835948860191,-4.15600767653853));
#547=CARTESIAN_POINT('',(0.428274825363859,-23.6133557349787,-4.39722047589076));
#548=CARTESIAN_POINT('',(0.213834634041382,-23.8277959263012,-4.51938331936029));
#549=CARTESIAN_POINT('',(-0.000199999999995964,-24.0418305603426,-4.64295303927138));
#550=B_SPLINE_CURVE_WITH_KNOTS('',3,(#506,#507,#508,#509,#510,#511,#512,#513,#514,#515,#516,
#517,#518,#519,#520,#521,#522,#523,#524,#525,#526,#527,#528,#529,#530,#531,#532,#533,#534,#535,
#536,#537,#538,#539,#540,#541,#542,#543,#544,#545,#546,#547,#548,#549),.UNSPECIFIED.,.F.,.F.,(4,
2,2,2,2,2,2,2,2,2,2,2,2,2,2,2,2,2,2,2,2,4),(0.,0.936579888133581,1.87317804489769,
3.74698468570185,5.6323516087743,7.5175585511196,11.2234409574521,13.0725100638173,
14.9213793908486,16.4685561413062,18.0156812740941,19.5634935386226,21.1113338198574,
22.6618861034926,24.2124689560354,25.7632734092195,27.3140430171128,29.2864587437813,
31.2582834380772,33.2199463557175,34.200794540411,35.1816139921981),.UNSPECIFIED.);
#551=CARTESIAN_POINT('',(0.,-24.0416305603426,-4.64283756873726));
#552=VERTEX_POINT('',#551);
#553=EDGE_CURVE('E82',#480,#552,#550,.T.);
#554=ORIENTED_EDGE('',*,*,#553,.T.);
#555=DIRECTION('',(0.,0.,1.));
#556=VECTOR('',#555,1.);
#557=CARTESIAN_POINT('',(0.,-24.0416305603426,-18.));
#558=LINE('',#557,#556);
#559=CARTESIAN_POINT('',(0.,-24.0416305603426,-18.));
#560=VERTEX_POINT('',#559);
#561=EDGE_CURVE('E100',#560,#552,#558,.T.);
#562=ORIENTED_EDGE('',*,*,#561,.F.);
#563=DIRECTION('',(0.707106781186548,0.707106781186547,0.));
#564=VECTOR('',#563,1.);
#565=CARTESIAN_POINT('',(0.,-24.0416305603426,-18.));
#566=LINE('',#565,#564);
#567=EDGE_CURVE('E98',#560,#488,#566,.T.);
#568=ORIENTED_EDGE('',*,*,#567,.T.);
#569=EDGE_LOOP('',(#505,#554,#562,#568));
#570=FACE_BOUND('',#569,.T.);
#571=ADVANCED_FACE('F96',(#570),#504,.T.);
#572=CARTESIAN_POINT('',(-24.0416305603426,0.,-18.));
#573=DIRECTION('',(-0.707106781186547,-0.707106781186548,0.));
#574=DIRECTION('',(0.707106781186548,-0.707106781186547,0.));
#575=AXIS2_PLACEMENT_3D('',#572,#573,#574);
#576=PLANE('',#575);
#577=ORIENTED_EDGE('',*,*,#561,.T.);
#578=CARTESIAN_POINT('',(0.000200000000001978,-24.0418305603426,-4.64295303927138));
#579=CARTESIAN_POINT('',(-0.20417991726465,-23.837450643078,-4.52495674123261));
#580=CARTESIAN_POINT('',(-0.408930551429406,-23.6327000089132,-4.40824356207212));
#581=CARTESIAN_POINT('',(-0.819230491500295,-23.2224000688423,-4.1776440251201));
#582=CARTESIAN_POINT('',(-1.02477981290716,-23.0168507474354,-4.06375772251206));
#583=CARTESIAN_POINT('',(-1.64283390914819,-22.3987966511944,-3.72666365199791));
#584=CARTESIAN_POINT('',(-2.05661170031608,-21.9850188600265,-3.50809795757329));
#585=CARTESIAN_POINT('',(-2.89055315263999,-21.1510774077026,-3.08458280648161));
#586=CARTESIAN_POINT('',(-3.3107404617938,-20.7308900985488,-2.87972567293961));
#587=CARTESIAN_POINT('',(-4.15527812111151,-19.8863524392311,-2.4883165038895));
#588=CARTESIAN_POINT('',(-4.57962811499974,-19.4620024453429,-2.30176291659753));
#589=CARTESIAN_POINT('',(-5.84524248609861,-18.196388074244,-1.78094350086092));
#590=CARTESIAN_POINT('',(-6.69335424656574,-17.3482763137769,-1.47802223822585));
#591=CARTESIAN_POINT('',(-7.97712947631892,-16.0645010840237,-1.11263624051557));
#592=CARTESIAN_POINT('',(-8.40653302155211,-15.6350975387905,-1.00573915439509));
#593=CARTESIAN_POINT('',(-9.26888168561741,-14.7727488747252,-0.825515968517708));
#594=CARTESIAN_POINT('',(-9.70182641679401,-14.3398041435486,-0.752186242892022));
#595=CARTESIAN_POINT('',(-10.4991978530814,-13.5424327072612,-0.651327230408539));
#596=CARTESIAN_POINT('',(-10.8632772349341,-13.1783533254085,-0.618276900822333));
#597=CARTESIAN_POINT('',(-11.592162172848,-12.4494683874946,-0.579101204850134));
#598=CARTESIAN_POINT('',(-11.9569677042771,-12.0846628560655,-0.572974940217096));
#599=CARTESIAN_POINT('',(-12.686458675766,-11.3551718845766,-0.587874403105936));
#600=CARTESIAN_POINT('',(-13.0511439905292,-10.9904865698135,-0.608912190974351));
#601=CARTESIAN_POINT('',(-13.7792651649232,-10.2623653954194,-0.677412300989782));
#602=CARTESIAN_POINT('',(-14.1427010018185,-9.89892955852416,-0.724875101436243));
#603=CARTESIAN_POINT('',(-14.868134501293,-9.17349605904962,-0.844749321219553));
#604=CARTESIAN_POINT('',(-15.2301285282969,-8.81150203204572,-0.917204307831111));
#605=CARTESIAN_POINT('',(-15.9514546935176,-8.09017586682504,-1.08487407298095));
#606=CARTESIAN_POINT('',(-16.3107867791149,-7.7308437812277,-1.18008930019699));
#607=CARTESIAN_POINT('',(-17.0264920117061,-7.0151385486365,-1.3908272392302));
#608=CARTESIAN_POINT('',(-17.3828647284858,-6.65876583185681,-1.50635285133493));
#609=CARTESIAN_POINT('',(-18.0924606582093,-5.94916990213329,-1.7551874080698));
#610=CARTESIAN_POINT('',(-18.44568394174,-5.59594661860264,-1.88849595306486));
#611=CARTESIAN_POINT('',(-19.244654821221,-4.79697573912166,-2.20884892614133));
#612=CARTESIAN_POINT('',(-19.689446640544,-4.35218391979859,-2.40064879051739));
#613=CARTESIAN_POINT('',(-20.5741726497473,-3.46745791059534,-2.80469605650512));
#614=CARTESIAN_POINT('',(-21.0141082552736,-3.02752230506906,-3.01693731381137));
#615=CARTESIAN_POINT('',(-21.8874677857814,-2.15416277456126,-3.45710309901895));
#616=CARTESIAN_POINT('',(-22.3209135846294,-1.72071697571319,-3.68494116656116));
#617=CARTESIAN_POINT('',(-22.968274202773,-1.07335635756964,-4.03695781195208));
#618=CARTESIAN_POINT('',(-23.1835948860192,-0.858035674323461,-4.15600767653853));
#619=CARTESIAN_POINT('',(-23.6133557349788,-0.428274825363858,-4.39722047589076));
#620=CARTESIAN_POINT('',(-23.8277959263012,-0.213834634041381,-4.51938331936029));
#621=CARTESIAN_POINT('',(-24.0418305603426,0.000199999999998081,-4.64295303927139));
#622=B_SPLINE_CURVE_WITH_KNOTS('',3,(#578,#579,#580,#581,#582,#583,#584,#585,#586,#587,#588,
#589,#590,#591,#592,#593,#594,#595,#596,#597,#598,#599,#600,#601,#602,#603,#604,#605,#606,#607,
#608,#609,#610,#611,#612,#613,#614,#615,#616,#617,#618,#619,#620,#621),.UNSPECIFIED.,.F.,.F.,(4,
2,2,2,2,2,2,2,2,2,2,2,2,2,2,2,2,2,2,2,2,4),(0.,0.93657988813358,1.8731780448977,
3.74698468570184,5.6323516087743,7.51755855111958,11.2234409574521,13.0725100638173,
14.9213793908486,16.4685561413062,18.015681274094,19.5634935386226,21.1113338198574,
22.6618861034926,24.2124689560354,25.7632734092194,27.3140430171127,29.2864587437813,
31.2582834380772,33.2199463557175,34.200794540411,35.1816139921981),.UNSPECIFIED.);
#623=CARTESIAN_POINT('',(-24.0416305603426,0.,-4.64283756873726));
#624=VERTEX_POINT('',#623);
#625=EDGE_CURVE('E86',#552,#624,#622,.T.);
#626=ORIENTED_EDGE('',*,*,#625,.T.);
#627=DIRECTION('',(0.,0.,1.));
#628=VECTOR('',#627,1.);
#629=CARTESIAN_POINT('',(-24.0416305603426,0.,-18.));
#630=LINE('',#629,#628);
#631=CARTESIAN_POINT('',(-24.0416305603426,0.,-18.));
#632=VERTEX_POINT('',#631);
#633=EDGE_CURVE('E104',#632,#624,#630,.T.);
#634=ORIENTED_EDGE('',*,*,#633,.F.);
#635=DIRECTION('',(0.707106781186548,-0.707106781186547,0.));
#636=VECTOR('',#635,1.);
#637=CARTESIAN_POINT('',(-24.0416305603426,0.,-18.));
#638=LINE('',#637,#636);
#639=EDGE_CURVE('E133',#632,#560,#638,.T.);
#640=ORIENTED_EDGE('',*,*,#639,.T.);
#641=EDGE_LOOP('',(#577,#626,#634,#640));
#642=FACE_BOUND('',#641,.T.);
#643=ADVANCED_FACE('F143',(#642),#576,.T.);
#644=CARTESIAN_POINT('',(0.,24.0416305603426,-18.));
#645=DIRECTION('',(-0.707106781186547,0.707106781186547,0.));
#646=DIRECTION('',(-0.707106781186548,-0.707106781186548,0.));
#647=AXIS2_PLACEMENT_3D('',#644,#645,#646);
#648=PLANE('',#647);
#649=ORIENTED_EDGE('',*,*,#633,.T.);
#650=CARTESIAN_POINT('',(-24.0418305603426,-0.000199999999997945,-4.64295303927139));
#651=CARTESIAN_POINT('',(-23.837450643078,0.204179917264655,-4.52495674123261));
#652=CARTESIAN_POINT('',(-23.6327000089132,0.408930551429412,-4.40824356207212));
#653=CARTESIAN_POINT('',(-23.2224000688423,0.819230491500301,-4.1776440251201));
#654=CARTESIAN_POINT('',(-23.0168507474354,1.02477981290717,-4.06375772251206));
#655=CARTESIAN_POINT('',(-22.3987966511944,1.64283390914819,-3.72666365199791));
#656=CARTESIAN_POINT('',(-21.9850188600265,2.05661170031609,-3.50809795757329));
#657=CARTESIAN_POINT('',(-21.1510774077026,2.89055315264,-3.08458280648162));
#658=CARTESIAN_POINT('',(-20.7308900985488,3.3107404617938,-2.87972567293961));
#659=CARTESIAN_POINT('',(-19.8863524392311,4.15527812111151,-2.4883165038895));
#660=CARTESIAN_POINT('',(-19.4620024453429,4.57962811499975,-2.30176291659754));
#661=CARTESIAN_POINT('',(-18.196388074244,5.84524248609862,-1.78094350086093));
#662=CARTESIAN_POINT('',(-17.3482763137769,6.69335424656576,-1.47802223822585));
#663=CARTESIAN_POINT('',(-16.0645010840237,7.97712947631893,-1.11263624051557));
#664=CARTESIAN_POINT('',(-15.6350975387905,8.40653302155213,-1.00573915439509));
#665=CARTESIAN_POINT('',(-14.7727488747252,9.26888168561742,-0.825515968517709));
#666=CARTESIAN_POINT('',(-14.3398041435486,9.70182641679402,-0.752186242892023));
#667=CARTESIAN_POINT('',(-13.5424327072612,10.4991978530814,-0.65132723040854));
#668=CARTESIAN_POINT('',(-13.1783533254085,10.8632772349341,-0.618276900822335));
#669=CARTESIAN_POINT('',(-12.4494683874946,11.592162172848,-0.579101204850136));
#670=CARTESIAN_POINT('',(-12.0846628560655,11.9569677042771,-0.572974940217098));
#671=CARTESIAN_POINT('',(-11.3551718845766,12.686458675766,-0.587874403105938));
#672=CARTESIAN_POINT('',(-10.9904865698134,13.0511439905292,-0.608912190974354));
#673=CARTESIAN_POINT('',(-10.2623653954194,13.7792651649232,-0.677412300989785));
#674=CARTESIAN_POINT('',(-9.89892955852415,14.1427010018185,-0.724875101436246));
#675=CARTESIAN_POINT('',(-9.17349605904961,14.868134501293,-0.844749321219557));
#676=CARTESIAN_POINT('',(-8.81150203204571,15.2301285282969,-0.917204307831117));
#677=CARTESIAN_POINT('',(-8.09017586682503,15.9514546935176,-1.08487407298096));
#678=CARTESIAN_POINT('',(-7.73084378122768,16.3107867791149,-1.180089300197));
#679=CARTESIAN_POINT('',(-7.01513854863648,17.0264920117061,-1.39082723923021));
#680=CARTESIAN_POINT('',(-6.65876583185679,17.3828647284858,-1.50635285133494));
#681=CARTESIAN_POINT('',(-5.94916990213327,18.0924606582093,-1.75518740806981));
#682=CARTESIAN_POINT('',(-5.59594661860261,18.44568394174,-1.88849595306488));
#683=CARTESIAN_POINT('',(-4.79697573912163,19.244654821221,-2.20884892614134));
#684=CARTESIAN_POINT('',(-4.35218391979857,19.689446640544,-2.4006487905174));
#685=CARTESIAN_POINT('',(-3.46745791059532,20.5741726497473,-2.80469605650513));
#686=CARTESIAN_POINT('',(-3.02752230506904,21.0141082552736,-3.01693731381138));
#687=CARTESIAN_POINT('',(-2.15416277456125,21.8874677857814,-3.45710309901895));
#688=CARTESIAN_POINT('',(-1.72071697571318,22.3209135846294,-3.68494116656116));
#689=CARTESIAN_POINT('',(-1.07335635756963,22.968274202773,-4.03695781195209));
#690=CARTESIAN_POINT('',(-0.858035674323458,23.1835948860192,-4.15600767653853));
#691=CARTESIAN_POINT('',(-0.428274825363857,23.6133557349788,-4.39722047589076));
#692=CARTESIAN_POINT('',(-0.213834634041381,23.8277959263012,-4.51938331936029));
#693=CARTESIAN_POINT('',(0.000199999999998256,24.0418305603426,-4.64295303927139));
#694=B_SPLINE_CURVE_WITH_KNOTS('',3,(#650,#651,#652,#653,#654,#655,#656,#657,#658,#659,#660,
#661,#662,#663,#664,#665,#666,#667,#668,#669,#670,#671,#672,#673,#674,#675,#676,#677,#678,#679,
#680,#681,#682,#683,#684,#685,#686,#687,#688,#689,#690,#691,#692,#693),.UNSPECIFIED.,.F.,.F.,(4,
2,2,2,2,2,2,2,2,2,2,2,2,2,2,2,2,2,2,2,2,4),(0.,0.936579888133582,1.8731780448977,
3.74698468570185,5.6323516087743,7.5175585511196,11.2234409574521,13.0725100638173,
14.9213793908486,16.4685561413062,18.0156812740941,19.5634935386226,21.1113338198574,
22.6618861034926,24.2124689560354,25.7632734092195,27.3140430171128,29.2864587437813,
31.2582834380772,33.2199463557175,34.200794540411,35.1816139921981),.UNSPECIFIED.);
#695=EDGE_CURVE('E146',#624,#431,#694,.T.);
#696=ORIENTED_EDGE('',*,*,#695,.T.);
#697=ORIENTED_EDGE('',*,*,#432,.F.);
#698=DIRECTION('',(-0.707106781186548,-0.707106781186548,0.));
#699=VECTOR('',#698,1.);
#700=CARTESIAN_POINT('',(0.,24.0416305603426,-18.));
#701=LINE('',#700,#699);
#702=EDGE_CURVE('E131',#429,#632,#701,.T.);
#703=ORIENTED_EDGE('',*,*,#702,.T.);
#704=EDGE_LOOP('',(#649,#696,#697,#703));
#705=FACE_BOUND('',#704,.T.);
#706=ADVANCED_FACE('F145',(#705),#648,.T.);
#707=CARTESIAN_POINT('',(0.,24.0416305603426,0.));
#708=DIRECTION('',(0.,0.,1.));
#709=DIRECTION('',(1.,0.,0.));
#710=AXIS2_PLACEMENT_3D('',#707,#708,#709);
#711=PLANE('',#710);
#712=ORIENTED_EDGE('',*,*,#335,.T.);
#713=EDGE_LOOP('',(#712));
#714=FACE_BOUND('',#713,.T.);
#715=CARTESIAN_POINT('',(0.,0.,0.));
#716=DIRECTION('',(0.,0.,1.));
#717=DIRECTION('',(1.,0.,0.));
#718=AXIS2_PLACEMENT_3D('',#715,#716,#717);
#719=CIRCLE('',#718,16.);
#720=CARTESIAN_POINT('',(16.,0.,0.));
#721=VERTEX_POINT('',#720);
#722=EDGE_CURVE('E147',#721,#721,#719,.T.);
#723=ORIENTED_EDGE('',*,*,#722,.T.);
#724=EDGE_LOOP('',(#723));
#725=FACE_BOUND('',#724,.T.);
#726=ADVANCED_FACE('F126',(#714,#725),#711,.T.);
#727=CARTESIAN_POINT('',(0.,24.0416305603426,-18.));
#728=DIRECTION('',(0.,0.,1.));
#729=DIRECTION('',(1.,0.,0.));
#730=AXIS2_PLACEMENT_3D('',#727,#728,#729);
#731=PLANE('',#730);
#732=CARTESIAN_POINT('',(0.,0.,-18.));
#733=DIRECTION('',(0.,0.,1.));
#734=DIRECTION('',(1.,0.,0.));
#735=AXIS2_PLACEMENT_3D('',#732,#733,#734);
#736=CIRCLE('',#735,11.2775);
#737=CARTESIAN_POINT('',(-11.2775,0.,-18.));
#738=VERTEX_POINT('',#737);
#739=EDGE_CURVE('E99',#738,#738,#736,.T.);
#740=ORIENTED_EDGE('',*,*,#739,.T.);
#741=EDGE_LOOP('',(#740));
#742=FACE_BOUND('',#741,.T.);
#743=ORIENTED_EDGE('',*,*,#495,.F.);
#744=ORIENTED_EDGE('',*,*,#567,.F.);
#745=ORIENTED_EDGE('',*,*,#639,.F.);
#746=ORIENTED_EDGE('',*,*,#702,.F.);
#747=EDGE_LOOP('',(#743,#744,#745,#746));
#748=FACE_BOUND('',#747,.T.);
#749=ADVANCED_FACE('F123',(#742,#748),#731,.F.);
#750=CARTESIAN_POINT('',(0.,0.,0.));
#751=DIRECTION('',(0.,0.,-1.));
#752=DIRECTION('',(-1.,0.,0.));
#753=AXIS2_PLACEMENT_3D('',#750,#751,#752);
#754=CONICAL_SURFACE('',#753,16.,1.0471975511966);
#755=ORIENTED_EDGE('',*,*,#695,.F.);
#756=ORIENTED_EDGE('',*,*,#625,.F.);
#757=ORIENTED_EDGE('',*,*,#553,.F.);
#758=ORIENTED_EDGE('',*,*,#481,.F.);
#759=EDGE_LOOP('',(#755,#756,#757,#758));
#760=FACE_BOUND('',#759,.T.);
#761=ORIENTED_EDGE('',*,*,#722,.F.);
#762=EDGE_LOOP('',(#761));
#763=FACE_BOUND('',#762,.T.);
#764=ADVANCED_FACE('F83',(#760,#763),#754,.T.);
#765=CARTESIAN_POINT('',(0.,0.,-18.));
#766=DIRECTION('',(0.,0.,-1.));
#767=DIRECTION('',(-1.,0.,0.));
#768=AXIS2_PLACEMENT_3D('',#765,#766,#767);
#769=CONICAL_SURFACE('',#768,11.2775,0.785398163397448);
#770=CARTESIAN_POINT('',(-9.9175,0.,-16.64));
#771=CARTESIAN_POINT('',(-9.93166666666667,0.,-16.6541666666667));
#772=CARTESIAN_POINT('',(-9.94583333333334,0.,-16.6683333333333));
#773=CARTESIAN_POINT('',(-9.97416666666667,0.,-16.6966666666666));
#774=CARTESIAN_POINT('',(-9.98833333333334,0.,-16.7108333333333));
#775=CARTESIAN_POINT('',(-10.0166666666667,0.,-16.7391666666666));
#776=CARTESIAN_POINT('',(-10.0308333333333,0.,-16.7533333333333));
#777=CARTESIAN_POINT('',(-10.0591666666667,0.,-16.7816666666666));
#778=CARTESIAN_POINT('',(-10.0733333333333,0.,-16.7958333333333));
#779=CARTESIAN_POINT('',(-10.1016666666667,0.,-16.8241666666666));
#780=CARTESIAN_POINT('',(-10.1158333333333,0.,-16.8383333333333));
#781=CARTESIAN_POINT('',(-10.1441666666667,0.,-16.8666666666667));
#782=CARTESIAN_POINT('',(-10.1583333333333,0.,-16.8808333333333));
#783=CARTESIAN_POINT('',(-10.1866666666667,0.,-16.9091666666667));
#784=CARTESIAN_POINT('',(-10.2008333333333,0.,-16.9233333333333));
#785=CARTESIAN_POINT('',(-10.2291666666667,0.,-16.9516666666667));
#786=CARTESIAN_POINT('',(-10.2433333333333,0.,-16.9658333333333));
#787=CARTESIAN_POINT('',(-10.2716666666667,0.,-16.9941666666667));
#788=CARTESIAN_POINT('',(-10.2858333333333,0.,-17.0083333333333));
#789=CARTESIAN_POINT('',(-10.3141666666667,0.,-17.0366666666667));
#790=CARTESIAN_POINT('',(-10.3283333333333,0.,-17.0508333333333));
#791=CARTESIAN_POINT('',(-10.3566666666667,0.,-17.0791666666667));
#792=CARTESIAN_POINT('',(-10.3708333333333,0.,-17.0933333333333));
#793=CARTESIAN_POINT('',(-10.3991666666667,0.,-17.1216666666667));
#794=CARTESIAN_POINT('',(-10.4133333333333,0.,-17.1358333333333));
#795=CARTESIAN_POINT('',(-10.4416666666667,0.,-17.1641666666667));
#796=CARTESIAN_POINT('',(-10.4558333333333,0.,-17.1783333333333));
#797=CARTESIAN_POINT('',(-10.4841666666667,0.,-17.2066666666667));
#798=CARTESIAN_POINT('',(-10.4983333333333,0.,-17.2208333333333));
#799=CARTESIAN_POINT('',(-10.5266666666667,0.,-17.2491666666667));
#800=CARTESIAN_POINT('',(-10.5408333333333,0.,-17.2633333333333));
#801=CARTESIAN_POINT('',(-10.5691666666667,0.,-17.2916666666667));
#802=CARTESIAN_POINT('',(-10.5833333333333,0.,-17.3058333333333));
#803=CARTESIAN_POINT('',(-10.6116666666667,0.,-17.3341666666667));
#804=CARTESIAN_POINT('',(-10.6258333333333,0.,-17.3483333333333));
#805=CARTESIAN_POINT('',(-10.6541666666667,0.,-17.3766666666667));
#806=CARTESIAN_POINT('',(-10.6683333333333,0.,-17.3908333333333));
#807=CARTESIAN_POINT('',(-10.6966666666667,0.,-17.4191666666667));
#808=CARTESIAN_POINT('',(-10.7108333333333,0.,-17.4333333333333));
#809=CARTESIAN_POINT('',(-10.7391666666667,0.,-17.4616666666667));
#810=CARTESIAN_POINT('',(-10.7533333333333,0.,-17.4758333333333));
#811=CARTESIAN_POINT('',(-10.7816666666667,0.,-17.5041666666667));
#812=CARTESIAN_POINT('',(-10.7958333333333,0.,-17.5183333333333));
#813=CARTESIAN_POINT('',(-10.8241666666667,0.,-17.5466666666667));
#814=CARTESIAN_POINT('',(-10.8383333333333,0.,-17.5608333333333));
#815=CARTESIAN_POINT('',(-10.8666666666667,0.,-17.5891666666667));
#816=CARTESIAN_POINT('',(-10.8808333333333,0.,-17.6033333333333));
#817=CARTESIAN_POINT('',(-10.9091666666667,0.,-17.6316666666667));
#818=CARTESIAN_POINT('',(-10.9233333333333,0.,-17.6458333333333));
#819=CARTESIAN_POINT('',(-10.9516666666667,0.,-17.6741666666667));
#820=CARTESIAN_POINT('',(-10.9658333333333,0.,-17.6883333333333));
#821=CARTESIAN_POINT('',(-10.9941666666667,0.,-17.7166666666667));
#822=CARTESIAN_POINT('',(-11.0083333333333,0.,-17.7308333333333));
#823=CARTESIAN_POINT('',(-11.0366666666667,0.,-17.7591666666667));
#824=CARTESIAN_POINT('',(-11.0508333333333,0.,-17.7733333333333));
#825=CARTESIAN_POINT('',(-11.0791666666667,0.,-17.8016666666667));
#826=CARTESIAN_POINT('',(-11.0933333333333,0.,-17.8158333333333));
#827=CARTESIAN_POINT('',(-11.1216666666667,0.,-17.8441666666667));
#828=CARTESIAN_POINT('',(-11.1358333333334,0.,-17.8583333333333));
#829=CARTESIAN_POINT('',(-11.1641666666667,0.,-17.8866666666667));
#830=CARTESIAN_POINT('',(-11.1783333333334,0.,-17.9008333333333));
#831=CARTESIAN_POINT('',(-11.2066666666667,0.,-17.9291666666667));
#832=CARTESIAN_POINT('',(-11.2208333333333,0.,-17.9433333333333));
#833=CARTESIAN_POINT('',(-11.2491666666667,0.,-17.9716666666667));
#834=CARTESIAN_POINT('',(-11.2633333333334,0.,-17.9858333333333));
#835=CARTESIAN_POINT('',(-11.2775,0.,-18.));
#836=B_SPLINE_CURVE_WITH_KNOTS('',3,(#770,#771,#772,#773,#774,#775,#776,#777,#778,#779,#780,
#781,#782,#783,#784,#785,#786,#787,#788,#789,#790,#791,#792,#793,#794,#795,#796,#797,#798,#799,
#800,#801,#802,#803,#804,#805,#806,#807,#808,#809,#810,#811,#812,#813,#814,#815,#816,#817,#818,
#819,#820,#821,#822,#823,#824,#825,#826,#827,#828,#829,#830,#831,#832,#833,#834,#835),
.UNSPECIFIED.,.F.,.F.,(4,2,2,2,2,2,2,2,2,2,2,2,2,2,2,2,2,2,2,2,2,2,2,2,2,2,2,2,2,2,2,2,4),(0.,
0.0601040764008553,0.120208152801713,0.18031222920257,0.240416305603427,0.300520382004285,
0.360624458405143,0.420728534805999,0.480832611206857,0.540936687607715,0.601040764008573,
0.661144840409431,0.721248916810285,0.781352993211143,0.841457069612,0.901561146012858,
0.961665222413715,1.02176929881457,1.08187337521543,1.14197745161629,1.20208152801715,
1.262185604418,1.32228968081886,1.38239375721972,1.44249783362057,1.50260191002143,
1.56270598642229,1.62281006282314,1.682914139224,1.74301821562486,1.80312229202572,
1.86322636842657,1.92333044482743),.UNSPECIFIED.);
#837=EDGE_CURVE('BSEAM117',#30,#738,#836,.T.);
#838=ORIENTED_EDGE('',*,*,#31,.F.);
#839=ORIENTED_EDGE('',*,*,#739,.F.);
#840=ORIENTED_EDGE('',*,*,#837,.T.);
#841=ORIENTED_EDGE('',*,*,#837,.F.);
#842=EDGE_LOOP('',(#838,#840,#839,#841));
#843=FACE_BOUND('',#842,.T.);
#844=ADVANCED_FACE('F117',(#843),#769,.F.);
#845=CARTESIAN_POINT('',(0.,0.,-1.36));
#846=DIRECTION('',(0.,0.,1.));
#847=DIRECTION('',(1.,0.,0.));
#848=AXIS2_PLACEMENT_3D('',#845,#846,#847);
#849=CONICAL_SURFACE('',#848,10.7763806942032,1.0471975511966);
#850=ORIENTED_EDGE('',*,*,#307,.T.);
#851=EDGE_LOOP('',(#850));
#852=FACE_BOUND('',#851,.T.);
#853=CARTESIAN_POINT('',(0.,0.,-1.36));
#854=DIRECTION('',(0.,0.,-1.));
#855=DIRECTION('',(-1.,0.,0.));
#856=AXIS2_PLACEMENT_3D('',#853,#854,#855);
#857=CIRCLE('',#856,10.7763806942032);
#858=CARTESIAN_POINT('',(-10.7763806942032,0.,-1.36));
#859=VERTEX_POINT('',#858);
#860=EDGE_CURVE('E226',#859,#859,#857,.T.);
#861=ORIENTED_EDGE('',*,*,#860,.F.);
#862=EDGE_LOOP('',(#861));
#863=FACE_BOUND('',#862,.T.);
#864=ADVANCED_FACE('F120',(#852,#863),#849,.F.);
#865=CARTESIAN_POINT('',(0.,0.,-0.864125));
#866=DIRECTION('',(0.,0.,-1.));
#867=DIRECTION('',(-1.,0.,0.));
#868=AXIS2_PLACEMENT_3D('',#865,#866,#867);
#869=CONICAL_SURFACE('',#868,9.9175,1.0471975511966);
#870=ORIENTED_EDGE('',*,*,#343,.F.);
#871=EDGE_LOOP('',(#870));
#872=FACE_BOUND('',#871,.T.);
#873=ORIENTED_EDGE('',*,*,#860,.T.);
#874=EDGE_LOOP('',(#873));
#875=FACE_BOUND('',#874,.T.);
#876=ADVANCED_FACE('F233',(#872,#875),#869,.F.);
#877=CARTESIAN_POINT('',(0.,0.,-2.5501));
#878=DIRECTION('',(0.,0.,1.));
#879=DIRECTION('',(1.,0.,0.));
#880=AXIS2_PLACEMENT_3D('',#877,#878,#879);
#881=CONICAL_SURFACE('',#880,10.7763806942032,1.0471975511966);
#882=ORIENTED_EDGE('',*,*,#284,.T.);
#883=EDGE_LOOP('',(#882));
#884=FACE_BOUND('',#883,.T.);
#885=CARTESIAN_POINT('',(0.,0.,-2.5501));
#886=DIRECTION('',(0.,0.,-1.));
#887=DIRECTION('',(-1.,0.,0.));
#888=AXIS2_PLACEMENT_3D('',#885,#886,#887);
#889=CIRCLE('',#888,10.7763806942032);
#890=CARTESIAN_POINT('',(-10.7763806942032,0.,-2.5501));
#891=VERTEX_POINT('',#890);
#892=EDGE_CURVE('E213',#891,#891,#889,.T.);
#893=ORIENTED_EDGE('',*,*,#892,.F.);
#894=EDGE_LOOP('',(#893));
#895=FACE_BOUND('',#894,.T.);
#896=ADVANCED_FACE('F235',(#884,#895),#881,.F.);
#897=CARTESIAN_POINT('',(0.,0.,-2.054225));
#898=DIRECTION('',(0.,0.,-1.));
#899=DIRECTION('',(-1.,0.,0.));
#900=AXIS2_PLACEMENT_3D('',#897,#898,#899);
#901=CONICAL_SURFACE('',#900,9.9175,1.0471975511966);
#902=ORIENTED_EDGE('',*,*,#892,.T.);
#903=EDGE_LOOP('',(#902));
#904=FACE_BOUND('',#903,.T.);
#905=ORIENTED_EDGE('',*,*,#318,.F.);
#906=EDGE_LOOP('',(#905));
#907=FACE_BOUND('',#906,.T.);
#908=ADVANCED_FACE('F352',(#904,#907),#901,.F.);
#909=CARTESIAN_POINT('',(0.,0.,-3.7402));
#910=DIRECTION('',(0.,0.,1.));
#911=DIRECTION('',(1.,0.,0.));
#912=AXIS2_PLACEMENT_3D('',#909,#910,#911);
#913=CONICAL_SURFACE('',#912,10.7763806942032,1.0471975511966);
#914=ORIENTED_EDGE('',*,*,#261,.T.);
#915=EDGE_LOOP('',(#914));
#916=FACE_BOUND('',#915,.T.);
#917=CARTESIAN_POINT('',(0.,0.,-3.7402));
#918=DIRECTION('',(0.,0.,-1.));
#919=DIRECTION('',(-1.,0.,0.));
#920=AXIS2_PLACEMENT_3D('',#917,#918,#919);
#921=CIRCLE('',#920,10.7763806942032);
#922=CARTESIAN_POINT('',(-10.7763806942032,0.,-3.7402));
#923=VERTEX_POINT('',#922);
#924=EDGE_CURVE('E220',#923,#923,#921,.T.);
#925=ORIENTED_EDGE('',*,*,#924,.F.);
#926=EDGE_LOOP('',(#925));
#927=FACE_BOUND('',#926,.T.);
#928=ADVANCED_FACE('F363',(#916,#927),#913,.F.);
#929=CARTESIAN_POINT('',(0.,0.,-3.244325));
#930=DIRECTION('',(0.,0.,-1.));
#931=DIRECTION('',(-1.,0.,0.));
#932=AXIS2_PLACEMENT_3D('',#929,#930,#931);
#933=CONICAL_SURFACE('',#932,9.9175,1.0471975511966);
#934=ORIENTED_EDGE('',*,*,#924,.T.);
#935=EDGE_LOOP('',(#934));
#936=FACE_BOUND('',#935,.T.);
#937=ORIENTED_EDGE('',*,*,#295,.F.);
#938=EDGE_LOOP('',(#937));
#939=FACE_BOUND('',#938,.T.);
#940=ADVANCED_FACE('F374',(#936,#939),#933,.F.);
#941=CARTESIAN_POINT('',(0.,0.,-4.9303));
#942=DIRECTION('',(0.,0.,1.));
#943=DIRECTION('',(1.,0.,0.));
#944=AXIS2_PLACEMENT_3D('',#941,#942,#943);
#945=CONICAL_SURFACE('',#944,10.7763806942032,1.0471975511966);
#946=ORIENTED_EDGE('',*,*,#238,.T.);
#947=EDGE_LOOP('',(#946));
#948=FACE_BOUND('',#947,.T.);
#949=CARTESIAN_POINT('',(0.,0.,-4.9303));
#950=DIRECTION('',(0.,0.,-1.));
#951=DIRECTION('',(-1.,0.,0.));
#952=AXIS2_PLACEMENT_3D('',#949,#950,#951);
#953=CIRCLE('',#952,10.7763806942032);
#954=CARTESIAN_POINT('',(-10.7763806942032,0.,-4.9303));
#955=VERTEX_POINT('',#954);
#956=EDGE_CURVE('E721',#955,#955,#953,.T.);
#957=ORIENTED_EDGE('',*,*,#956,.F.);
#958=EDGE_LOOP('',(#957));
#959=FACE_BOUND('',#958,.T.);
#960=ADVANCED_FACE('F385',(#948,#959),#945,.F.);
#961=CARTESIAN_POINT('',(0.,0.,-4.434425));
#962=DIRECTION('',(0.,0.,-1.));
#963=DIRECTION('',(-1.,0.,0.));
#964=AXIS2_PLACEMENT_3D('',#961,#962,#963);
#965=CONICAL_SURFACE('',#964,9.9175,1.0471975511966);
#966=ORIENTED_EDGE('',*,*,#956,.T.);
#967=EDGE_LOOP('',(#966));
#968=FACE_BOUND('',#967,.T.);
#969=ORIENTED_EDGE('',*,*,#272,.F.);
#970=EDGE_LOOP('',(#969));
#971=FACE_BOUND('',#970,.T.);
#972=ADVANCED_FACE('F396',(#968,#971),#965,.F.);
#973=CARTESIAN_POINT('',(0.,0.,-6.1204));
#974=DIRECTION('',(0.,0.,1.));
#975=DIRECTION('',(1.,0.,0.));
#976=AXIS2_PLACEMENT_3D('',#973,#974,#975);
#977=CONICAL_SURFACE('',#976,10.7763806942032,1.0471975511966);
#978=ORIENTED_EDGE('',*,*,#215,.T.);
#979=EDGE_LOOP('',(#978));
#980=FACE_BOUND('',#979,.T.);
#981=CARTESIAN_POINT('',(0.,0.,-6.1204));
#982=DIRECTION('',(0.,0.,-1.));
#983=DIRECTION('',(-1.,0.,0.));
#984=AXIS2_PLACEMENT_3D('',#981,#982,#983);
#985=CIRCLE('',#984,10.7763806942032);
#986=CARTESIAN_POINT('',(-10.7763806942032,0.,-6.1204));
#987=VERTEX_POINT('',#986);
#988=EDGE_CURVE('E712',#987,#987,#985,.T.);
#989=ORIENTED_EDGE('',*,*,#988,.F.);
#990=EDGE_LOOP('',(#989));
#991=FACE_BOUND('',#990,.T.);
#992=ADVANCED_FACE('F407',(#980,#991),#977,.F.);
#993=CARTESIAN_POINT('',(0.,0.,-5.624525));
#994=DIRECTION('',(0.,0.,-1.));
#995=DIRECTION('',(-1.,0.,0.));
#996=AXIS2_PLACEMENT_3D('',#993,#994,#995);
#997=CONICAL_SURFACE('',#996,9.9175,1.0471975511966);
#998=ORIENTED_EDGE('',*,*,#988,.T.);
#999=EDGE_LOOP('',(#998));
#1000=FACE_BOUND('',#999,.T.);
#1001=ORIENTED_EDGE('',*,*,#249,.F.);
#1002=EDGE_LOOP('',(#1001));
#1003=FACE_BOUND('',#1002,.T.);
#1004=ADVANCED_FACE('F418',(#1000,#1003),#997,.F.);
#1005=CARTESIAN_POINT('',(0.,0.,-7.3105));
#1006=DIRECTION('',(0.,0.,1.));
#1007=DIRECTION('',(1.,0.,0.));
#1008=AXIS2_PLACEMENT_3D('',#1005,#1006,#1007);
#1009=CONICAL_SURFACE('',#1008,10.7763806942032,1.0471975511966);
#1010=ORIENTED_EDGE('',*,*,#192,.T.);
#1011=EDGE_LOOP('',(#1010));
#1012=FACE_BOUND('',#1011,.T.);
#1013=CARTESIAN_POINT('',(0.,0.,-7.3105));
#1014=DIRECTION('',(0.,0.,-1.));
#1015=DIRECTION('',(-1.,0.,0.));
#1016=AXIS2_PLACEMENT_3D('',#1013,#1014,#1015);
#1017=CIRCLE('',#1016,10.7763806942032);
#1018=CARTESIAN_POINT('',(-10.7763806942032,0.,-7.3105));
#1019=VERTEX_POINT('',#1018);
#1020=EDGE_CURVE('E703',#1019,#1019,#1017,.T.);
#1021=ORIENTED_EDGE('',*,*,#1020,.F.);
#1022=EDGE_LOOP('',(#1021));
#1023=FACE_BOUND('',#1022,.T.);
#1024=ADVANCED_FACE('F429',(#1012,#1023),#1009,.F.);
#1025=CARTESIAN_POINT('',(0.,0.,-6.814625));
#1026=DIRECTION('',(0.,0.,-1.));
#1027=DIRECTION('',(-1.,0.,0.));
#1028=AXIS2_PLACEMENT_3D('',#1025,#1026,#1027);
#1029=CONICAL_SURFACE('',#1028,9.9175,1.0471975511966);
#1030=ORIENTED_EDGE('',*,*,#1020,.T.);
#1031=EDGE_LOOP('',(#1030));
#1032=FACE_BOUND('',#1031,.T.);
#1033=ORIENTED_EDGE('',*,*,#226,.F.);
#1034=EDGE_LOOP('',(#1033));
#1035=FACE_BOUND('',#1034,.T.);
#1036=ADVANCED_FACE('F440',(#1032,#1035),#1029,.F.);
#1037=CARTESIAN_POINT('',(0.,0.,-8.5006));
#1038=DIRECTION('',(0.,0.,1.));
#1039=DIRECTION('',(1.,0.,0.));
#1040=AXIS2_PLACEMENT_3D('',#1037,#1038,#1039);
#1041=CONICAL_SURFACE('',#1040,10.7763806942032,1.0471975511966);
#1042=ORIENTED_EDGE('',*,*,#169,.T.);
#1043=EDGE_LOOP('',(#1042));
#1044=FACE_BOUND('',#1043,.T.);
#1045=CARTESIAN_POINT('',(0.,0.,-8.5006));
#1046=DIRECTION('',(0.,0.,-1.));
#1047=DIRECTION('',(-1.,0.,0.));
#1048=AXIS2_PLACEMENT_3D('',#1045,#1046,#1047);
#1049=CIRCLE('',#1048,10.7763806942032);
#1050=CARTESIAN_POINT('',(-10.7763806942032,0.,-8.5006));
#1051=VERTEX_POINT('',#1050);
#1052=EDGE_CURVE('E694',#1051,#1051,#1049,.T.);
#1053=ORIENTED_EDGE('',*,*,#1052,.F.);
#1054=EDGE_LOOP('',(#1053));
#1055=FACE_BOUND('',#1054,.T.);
#1056=ADVANCED_FACE('F451',(#1044,#1055),#1041,.F.);
#1057=CARTESIAN_POINT('',(0.,0.,-8.004725));
#1058=DIRECTION('',(0.,0.,-1.));
#1059=DIRECTION('',(-1.,0.,0.));
#1060=AXIS2_PLACEMENT_3D('',#1057,#1058,#1059);
#1061=CONICAL_SURFACE('',#1060,9.9175,1.0471975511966);
#1062=ORIENTED_EDGE('',*,*,#1052,.T.);
#1063=EDGE_LOOP('',(#1062));
#1064=FACE_BOUND('',#1063,.T.);
#1065=ORIENTED_EDGE('',*,*,#203,.F.);
#1066=EDGE_LOOP('',(#1065));
#1067=FACE_BOUND('',#1066,.T.);
#1068=ADVANCED_FACE('F462',(#1064,#1067),#1061,.F.);
#1069=CARTESIAN_POINT('',(0.,0.,-9.6907));
#1070=DIRECTION('',(0.,0.,1.));
#1071=DIRECTION('',(1.,0.,0.));
#1072=AXIS2_PLACEMENT_3D('',#1069,#1070,#1071);
#1073=CONICAL_SURFACE('',#1072,10.7763806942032,1.0471975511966);
#1074=ORIENTED_EDGE('',*,*,#146,.T.);
#1075=EDGE_LOOP('',(#1074));
#1076=FACE_BOUND('',#1075,.T.);
#1077=CARTESIAN_POINT('',(0.,0.,-9.6907));
#1078=DIRECTION('',(0.,0.,-1.));
#1079=DIRECTION('',(-1.,0.,0.));
#1080=AXIS2_PLACEMENT_3D('',#1077,#1078,#1079);
#1081=CIRCLE('',#1080,10.7763806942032);
#1082=CARTESIAN_POINT('',(-10.7763806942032,0.,-9.6907));
#1083=VERTEX_POINT('',#1082);
#1084=EDGE_CURVE('E685',#1083,#1083,#1081,.T.);
#1085=ORIENTED_EDGE('',*,*,#1084,.F.);
#1086=EDGE_LOOP('',(#1085));
#1087=FACE_BOUND('',#1086,.T.);
#1088=ADVANCED_FACE('F473',(#1076,#1087),#1073,.F.);
#1089=CARTESIAN_POINT('',(0.,0.,-9.194825));
#1090=DIRECTION('',(0.,0.,-1.));
#1091=DIRECTION('',(-1.,0.,0.));
#1092=AXIS2_PLACEMENT_3D('',#1089,#1090,#1091);
#1093=CONICAL_SURFACE('',#1092,9.9175,1.0471975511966);
#1094=ORIENTED_EDGE('',*,*,#1084,.T.);
#1095=EDGE_LOOP('',(#1094));
#1096=FACE_BOUND('',#1095,.T.);
#1097=ORIENTED_EDGE('',*,*,#180,.F.);
#1098=EDGE_LOOP('',(#1097));
#1099=FACE_BOUND('',#1098,.T.);
#1100=ADVANCED_FACE('F484',(#1096,#1099),#1093,.F.);
#1101=CARTESIAN_POINT('',(0.,0.,-10.8808));
#1102=DIRECTION('',(0.,0.,1.));
#1103=DIRECTION('',(1.,0.,0.));
#1104=AXIS2_PLACEMENT_3D('',#1101,#1102,#1103);
#1105=CONICAL_SURFACE('',#1104,10.7763806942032,1.0471975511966);
#1106=ORIENTED_EDGE('',*,*,#123,.T.);
#1107=EDGE_LOOP('',(#1106));
#1108=FACE_BOUND('',#1107,.T.);
#1109=CARTESIAN_POINT('',(0.,0.,-10.8808));
#1110=DIRECTION('',(0.,0.,-1.));
#1111=DIRECTION('',(-1.,0.,0.));
#1112=AXIS2_PLACEMENT_3D('',#1109,#1110,#1111);
#1113=CIRCLE('',#1112,10.7763806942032);
#1114=CARTESIAN_POINT('',(-10.7763806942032,0.,-10.8808));
#1115=VERTEX_POINT('',#1114);
#1116=EDGE_CURVE('E676',#1115,#1115,#1113,.T.);
#1117=ORIENTED_EDGE('',*,*,#1116,.F.);
#1118=EDGE_LOOP('',(#1117));
#1119=FACE_BOUND('',#1118,.T.);
#1120=ADVANCED_FACE('F495',(#1108,#1119),#1105,.F.);
#1121=CARTESIAN_POINT('',(0.,0.,-10.384925));
#1122=DIRECTION('',(0.,0.,-1.));
#1123=DIRECTION('',(-1.,0.,0.));
#1124=AXIS2_PLACEMENT_3D('',#1121,#1122,#1123);
#1125=CONICAL_SURFACE('',#1124,9.9175,1.0471975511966);
#1126=ORIENTED_EDGE('',*,*,#1116,.T.);
#1127=EDGE_LOOP('',(#1126));
#1128=FACE_BOUND('',#1127,.T.);
#1129=ORIENTED_EDGE('',*,*,#157,.F.);
#1130=EDGE_LOOP('',(#1129));
#1131=FACE_BOUND('',#1130,.T.);
#1132=ADVANCED_FACE('F506',(#1128,#1131),#1125,.F.);
#1133=CARTESIAN_POINT('',(0.,0.,-12.0709));
#1134=DIRECTION('',(0.,0.,1.));
#1135=DIRECTION('',(1.,0.,0.));
#1136=AXIS2_PLACEMENT_3D('',#1133,#1134,#1135);
#1137=CONICAL_SURFACE('',#1136,10.7763806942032,1.0471975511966);
#1138=ORIENTED_EDGE('',*,*,#100,.T.);
#1139=EDGE_LOOP('',(#1138));
#1140=FACE_BOUND('',#1139,.T.);
#1141=CARTESIAN_POINT('',(0.,0.,-12.0709));
#1142=DIRECTION('',(0.,0.,-1.));
#1143=DIRECTION('',(-1.,0.,0.));
#1144=AXIS2_PLACEMENT_3D('',#1141,#1142,#1143);
#1145=CIRCLE('',#1144,10.7763806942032);
#1146=CARTESIAN_POINT('',(-10.7763806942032,0.,-12.0709));
#1147=VERTEX_POINT('',#1146);
#1148=EDGE_CURVE('E667',#1147,#1147,#1145,.T.);
#1149=ORIENTED_EDGE('',*,*,#1148,.F.);
#1150=EDGE_LOOP('',(#1149));
#1151=FACE_BOUND('',#1150,.T.);
#1152=ADVANCED_FACE('F517',(#1140,#1151),#1137,.F.);
#1153=CARTESIAN_POINT('',(0.,0.,-11.575025));
#1154=DIRECTION('',(0.,0.,-1.));
#1155=DIRECTION('',(-1.,0.,0.));
#1156=AXIS2_PLACEMENT_3D('',#1153,#1154,#1155);
#1157=CONICAL_SURFACE('',#1156,9.9175,1.0471975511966);
#1158=ORIENTED_EDGE('',*,*,#1148,.T.);
#1159=EDGE_LOOP('',(#1158));
#1160=FACE_BOUND('',#1159,.T.);
#1161=ORIENTED_EDGE('',*,*,#134,.F.);
#1162=EDGE_LOOP('',(#1161));
#1163=FACE_BOUND('',#1162,.T.);
#1164=ADVANCED_FACE('F528',(#1160,#1163),#1157,.F.);
#1165=CARTESIAN_POINT('',(0.,0.,-13.261));
#1166=DIRECTION('',(0.,0.,1.));
#1167=DIRECTION('',(1.,0.,0.));
#1168=AXIS2_PLACEMENT_3D('',#1165,#1166,#1167);
#1169=CONICAL_SURFACE('',#1168,10.7763806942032,1.0471975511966);
#1170=ORIENTED_EDGE('',*,*,#77,.T.);
#1171=EDGE_LOOP('',(#1170));
#1172=FACE_BOUND('',#1171,.T.);
#1173=CARTESIAN_POINT('',(0.,0.,-13.261));
#1174=DIRECTION('',(0.,0.,-1.));
#1175=DIRECTION('',(-1.,0.,0.));
#1176=AXIS2_PLACEMENT_3D('',#1173,#1174,#1175);
#1177=CIRCLE('',#1176,10.7763806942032);
#1178=CARTESIAN_POINT('',(-10.7763806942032,0.,-13.261));
#1179=VERTEX_POINT('',#1178);
#1180=EDGE_CURVE('E658',#1179,#1179,#1177,.T.);
#1181=ORIENTED_EDGE('',*,*,#1180,.F.);
#1182=EDGE_LOOP('',(#1181));
#1183=FACE_BOUND('',#1182,.T.);
#1184=ADVANCED_FACE('F539',(#1172,#1183),#1169,.F.);
#1185=CARTESIAN_POINT('',(0.,0.,-12.765125));
#1186=DIRECTION('',(0.,0.,-1.));
#1187=DIRECTION('',(-1.,0.,0.));
#1188=AXIS2_PLACEMENT_3D('',#1185,#1186,#1187);
#1189=CONICAL_SURFACE('',#1188,9.9175,1.0471975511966);
#1190=ORIENTED_EDGE('',*,*,#1180,.T.);
#1191=EDGE_LOOP('',(#1190));
#1192=FACE_BOUND('',#1191,.T.);
#1193=ORIENTED_EDGE('',*,*,#111,.F.);
#1194=EDGE_LOOP('',(#1193));
#1195=FACE_BOUND('',#1194,.T.);
#1196=ADVANCED_FACE('F550',(#1192,#1195),#1189,.F.);
#1197=CARTESIAN_POINT('',(0.,0.,-14.4511));
#1198=DIRECTION('',(0.,0.,1.));
#1199=DIRECTION('',(1.,0.,0.));
#1200=AXIS2_PLACEMENT_3D('',#1197,#1198,#1199);
#1201=CONICAL_SURFACE('',#1200,10.7763806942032,1.0471975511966);
#1202=ORIENTED_EDGE('',*,*,#54,.T.);
#1203=EDGE_LOOP('',(#1202));
#1204=FACE_BOUND('',#1203,.T.);
#1205=CARTESIAN_POINT('',(0.,0.,-14.4511));
#1206=DIRECTION('',(0.,0.,-1.));
#1207=DIRECTION('',(-1.,0.,0.));
#1208=AXIS2_PLACEMENT_3D('',#1205,#1206,#1207);
#1209=CIRCLE('',#1208,10.7763806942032);
#1210=CARTESIAN_POINT('',(-10.7763806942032,0.,-14.4511));
#1211=VERTEX_POINT('',#1210);
#1212=EDGE_CURVE('E649',#1211,#1211,#1209,.T.);
#1213=ORIENTED_EDGE('',*,*,#1212,.F.);
#1214=EDGE_LOOP('',(#1213));
#1215=FACE_BOUND('',#1214,.T.);
#1216=ADVANCED_FACE('F561',(#1204,#1215),#1201,.F.);
#1217=CARTESIAN_POINT('',(0.,0.,-13.955225));
#1218=DIRECTION('',(0.,0.,-1.));
#1219=DIRECTION('',(-1.,0.,0.));
#1220=AXIS2_PLACEMENT_3D('',#1217,#1218,#1219);
#1221=CONICAL_SURFACE('',#1220,9.9175,1.0471975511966);
#1222=ORIENTED_EDGE('',*,*,#1212,.T.);
#1223=EDGE_LOOP('',(#1222));
#1224=FACE_BOUND('',#1223,.T.);
#1225=ORIENTED_EDGE('',*,*,#88,.F.);
#1226=EDGE_LOOP('',(#1225));
#1227=FACE_BOUND('',#1226,.T.);
#1228=ADVANCED_FACE('F572',(#1224,#1227),#1221,.F.);
#1229=CARTESIAN_POINT('',(0.,0.,-15.6412));
#1230=DIRECTION('',(0.,0.,1.));
#1231=DIRECTION('',(1.,0.,0.));
#1232=AXIS2_PLACEMENT_3D('',#1229,#1230,#1231);
#1233=CONICAL_SURFACE('',#1232,10.7763806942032,1.0471975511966);
#1234=ORIENTED_EDGE('',*,*,#42,.T.);
#1235=EDGE_LOOP('',(#1234));
#1236=FACE_BOUND('',#1235,.T.);
#1237=CARTESIAN_POINT('',(0.,0.,-15.6412));
#1238=DIRECTION('',(0.,0.,-1.));
#1239=DIRECTION('',(-1.,0.,0.));
#1240=AXIS2_PLACEMENT_3D('',#1237,#1238,#1239);
#1241=CIRCLE('',#1240,10.7763806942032);
#1242=CARTESIAN_POINT('',(-10.7763806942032,0.,-15.6412));
#1243=VERTEX_POINT('',#1242);
#1244=EDGE_CURVE('E635',#1243,#1243,#1241,.T.);
#1245=ORIENTED_EDGE('',*,*,#1244,.F.);
#1246=EDGE_LOOP('',(#1245));
#1247=FACE_BOUND('',#1246,.T.);
#1248=ADVANCED_FACE('F583',(#1236,#1247),#1233,.F.);
#1249=CARTESIAN_POINT('',(0.,0.,-15.145325));
#1250=DIRECTION('',(0.,0.,-1.));
#1251=DIRECTION('',(-1.,0.,0.));
#1252=AXIS2_PLACEMENT_3D('',#1249,#1250,#1251);
#1253=CONICAL_SURFACE('',#1252,9.9175,1.0471975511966);
#1254=ORIENTED_EDGE('',*,*,#1244,.T.);
#1255=EDGE_LOOP('',(#1254));
#1256=FACE_BOUND('',#1255,.T.);
#1257=ORIENTED_EDGE('',*,*,#65,.F.);
#1258=EDGE_LOOP('',(#1257));
#1259=FACE_BOUND('',#1258,.T.);
#1260=ADVANCED_FACE('F594',(#1256,#1259),#1253,.F.);
#1261=CLOSED_SHELL('',(#46,#69,#92,#115,#138,#161,#184,#207,#230,#253,#276,#299,#322,#418,#499,
#571,#643,#706,#726,#749,#764,#844,#864,#876,#896,#908,#928,#940,#960,#972,#992,#1004,#1024,
#1036,#1056,#1068,#1088,#1100,#1120,#1132,#1152,#1164,#1184,#1196,#1216,#1228,#1248,#1260));
#1262=MANIFOLD_SOLID_BREP('B2',#1261);
#1263=ADVANCED_BREP_SHAPE_REPRESENTATION('',(#18,#1262),#14);
#1264=SHAPE_DEFINITION_REPRESENTATION(#9,#1263);
ENDSEC;
END-ISO-10303-21;
